VERSION 5.8 ;
BUSBITCHARS "[]" ;
DIVIDERCHAR "/" ;
UNITS
    DATABASE MICRONS 1000 ;
END UNITS

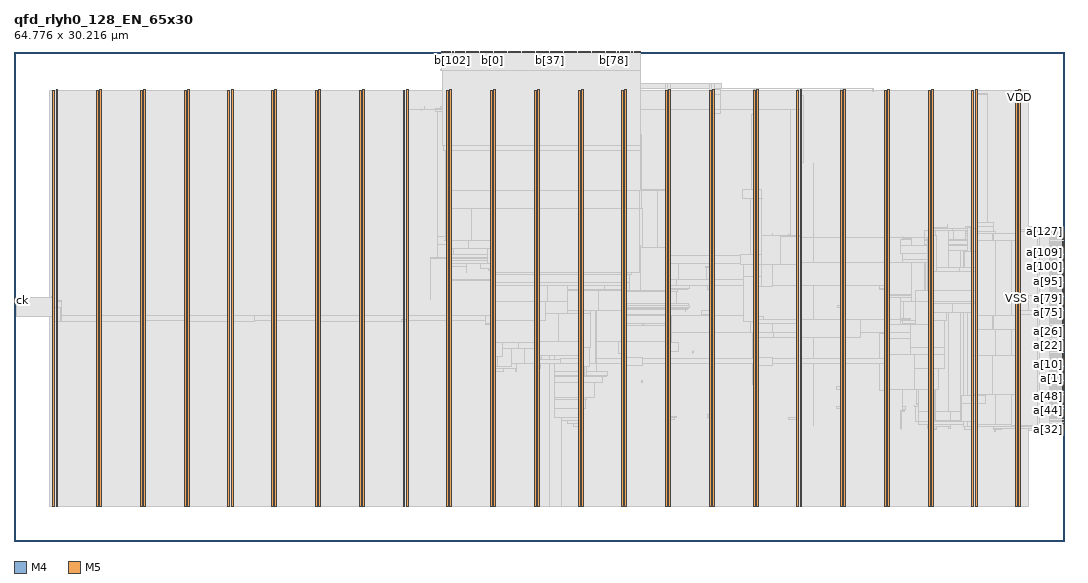
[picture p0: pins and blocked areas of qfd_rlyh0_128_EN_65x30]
MACRO qfd_rlyh0_128_EN_65x30
  FOREIGN qfd_rlyh0_128_EN_65x30 0 0 ;
  CLASS BLOCK ;
  SIZE 64.776 BY 30.216 ;
  PIN a[0]
    DIRECTION INPUT ;
    USE SIGNAL ;
    PORT
      LAYER M4 ;
        RECT  64.692 9.936 64.776 9.96 ;
    END
  END a[0]
  PIN a[100]
    DIRECTION INPUT ;
    USE SIGNAL ;
    PORT
      LAYER M4 ;
        RECT  64.692 16.464 64.776 16.488 ;
    END
  END a[100]
  PIN a[101]
    DIRECTION INPUT ;
    USE SIGNAL ;
    PORT
      LAYER M4 ;
        RECT  64.692 16.56 64.776 16.584 ;
    END
  END a[101]
  PIN a[102]
    DIRECTION INPUT ;
    USE SIGNAL ;
    PORT
      LAYER M4 ;
        RECT  64.692 16.656 64.776 16.68 ;
    END
  END a[102]
  PIN a[103]
    DIRECTION INPUT ;
    USE SIGNAL ;
    PORT
      LAYER M4 ;
        RECT  64.692 16.752 64.776 16.776 ;
    END
  END a[103]
  PIN a[104]
    DIRECTION INPUT ;
    USE SIGNAL ;
    PORT
      LAYER M4 ;
        RECT  64.692 16.848 64.776 16.872 ;
    END
  END a[104]
  PIN a[105]
    DIRECTION INPUT ;
    USE SIGNAL ;
    PORT
      LAYER M4 ;
        RECT  64.692 16.944 64.776 16.968 ;
    END
  END a[105]
  PIN a[106]
    DIRECTION INPUT ;
    USE SIGNAL ;
    PORT
      LAYER M4 ;
        RECT  64.692 17.04 64.776 17.064 ;
    END
  END a[106]
  PIN a[107]
    DIRECTION INPUT ;
    USE SIGNAL ;
    PORT
      LAYER M4 ;
        RECT  64.692 17.136 64.776 17.16 ;
    END
  END a[107]
  PIN a[108]
    DIRECTION INPUT ;
    USE SIGNAL ;
    PORT
      LAYER M4 ;
        RECT  64.692 17.232 64.776 17.256 ;
    END
  END a[108]
  PIN a[109]
    DIRECTION INPUT ;
    USE SIGNAL ;
    PORT
      LAYER M4 ;
        RECT  64.692 17.328 64.776 17.352 ;
    END
  END a[109]
  PIN a[10]
    DIRECTION INPUT ;
    USE SIGNAL ;
    PORT
      LAYER M4 ;
        RECT  64.692 10.896 64.776 10.92 ;
    END
  END a[10]
  PIN a[110]
    DIRECTION INPUT ;
    USE SIGNAL ;
    PORT
      LAYER M4 ;
        RECT  64.692 17.424 64.776 17.448 ;
    END
  END a[110]
  PIN a[111]
    DIRECTION INPUT ;
    USE SIGNAL ;
    PORT
      LAYER M4 ;
        RECT  64.692 17.52 64.776 17.544 ;
    END
  END a[111]
  PIN a[112]
    DIRECTION INPUT ;
    USE SIGNAL ;
    PORT
      LAYER M4 ;
        RECT  64.692 17.616 64.776 17.64 ;
    END
  END a[112]
  PIN a[113]
    DIRECTION INPUT ;
    USE SIGNAL ;
    PORT
      LAYER M4 ;
        RECT  64.692 17.712 64.776 17.736 ;
    END
  END a[113]
  PIN a[114]
    DIRECTION INPUT ;
    USE SIGNAL ;
    PORT
      LAYER M4 ;
        RECT  64.692 17.808 64.776 17.832 ;
    END
  END a[114]
  PIN a[115]
    DIRECTION INPUT ;
    USE SIGNAL ;
    PORT
      LAYER M4 ;
        RECT  64.692 17.904 64.776 17.928 ;
    END
  END a[115]
  PIN a[116]
    DIRECTION INPUT ;
    USE SIGNAL ;
    PORT
      LAYER M4 ;
        RECT  64.692 18 64.776 18.024 ;
    END
  END a[116]
  PIN a[117]
    DIRECTION INPUT ;
    USE SIGNAL ;
    PORT
      LAYER M4 ;
        RECT  64.692 18.096 64.776 18.12 ;
    END
  END a[117]
  PIN a[118]
    DIRECTION INPUT ;
    USE SIGNAL ;
    PORT
      LAYER M4 ;
        RECT  64.692 18.192 64.776 18.216 ;
    END
  END a[118]
  PIN a[119]
    DIRECTION INPUT ;
    USE SIGNAL ;
    PORT
      LAYER M4 ;
        RECT  64.692 18.288 64.776 18.312 ;
    END
  END a[119]
  PIN a[11]
    DIRECTION INPUT ;
    USE SIGNAL ;
    PORT
      LAYER M4 ;
        RECT  64.692 10.992 64.776 11.016 ;
    END
  END a[11]
  PIN a[120]
    DIRECTION INPUT ;
    USE SIGNAL ;
    PORT
      LAYER M4 ;
        RECT  64.692 18.384 64.776 18.408 ;
    END
  END a[120]
  PIN a[121]
    DIRECTION INPUT ;
    USE SIGNAL ;
    PORT
      LAYER M4 ;
        RECT  64.692 18.48 64.776 18.504 ;
    END
  END a[121]
  PIN a[122]
    DIRECTION INPUT ;
    USE SIGNAL ;
    PORT
      LAYER M4 ;
        RECT  64.692 18.576 64.776 18.6 ;
    END
  END a[122]
  PIN a[123]
    DIRECTION INPUT ;
    USE SIGNAL ;
    PORT
      LAYER M4 ;
        RECT  64.692 18.672 64.776 18.696 ;
    END
  END a[123]
  PIN a[124]
    DIRECTION INPUT ;
    USE SIGNAL ;
    PORT
      LAYER M4 ;
        RECT  64.692 18.768 64.776 18.792 ;
    END
  END a[124]
  PIN a[125]
    DIRECTION INPUT ;
    USE SIGNAL ;
    PORT
      LAYER M4 ;
        RECT  64.692 18.864 64.776 18.888 ;
    END
  END a[125]
  PIN a[126]
    DIRECTION INPUT ;
    USE SIGNAL ;
    PORT
      LAYER M4 ;
        RECT  64.692 18.96 64.776 18.984 ;
    END
  END a[126]
  PIN a[127]
    DIRECTION INPUT ;
    USE SIGNAL ;
    PORT
      LAYER M4 ;
        RECT  64.692 19.056 64.776 19.08 ;
    END
  END a[127]
  PIN a[12]
    DIRECTION INPUT ;
    USE SIGNAL ;
    PORT
      LAYER M4 ;
        RECT  64.692 11.088 64.776 11.112 ;
    END
  END a[12]
  PIN a[13]
    DIRECTION INPUT ;
    USE SIGNAL ;
    PORT
      LAYER M4 ;
        RECT  64.692 11.184 64.776 11.208 ;
    END
  END a[13]
  PIN a[14]
    DIRECTION INPUT ;
    USE SIGNAL ;
    PORT
      LAYER M4 ;
        RECT  64.692 11.28 64.776 11.304 ;
    END
  END a[14]
  PIN a[15]
    DIRECTION INPUT ;
    USE SIGNAL ;
    PORT
      LAYER M4 ;
        RECT  64.692 11.376 64.776 11.4 ;
    END
  END a[15]
  PIN a[16]
    DIRECTION INPUT ;
    USE SIGNAL ;
    PORT
      LAYER M4 ;
        RECT  64.692 11.472 64.776 11.496 ;
    END
  END a[16]
  PIN a[17]
    DIRECTION INPUT ;
    USE SIGNAL ;
    PORT
      LAYER M4 ;
        RECT  64.692 11.568 64.776 11.592 ;
    END
  END a[17]
  PIN a[18]
    DIRECTION INPUT ;
    USE SIGNAL ;
    PORT
      LAYER M4 ;
        RECT  64.692 11.664 64.776 11.688 ;
    END
  END a[18]
  PIN a[19]
    DIRECTION INPUT ;
    USE SIGNAL ;
    PORT
      LAYER M4 ;
        RECT  64.692 11.76 64.776 11.784 ;
    END
  END a[19]
  PIN a[1]
    DIRECTION INPUT ;
    USE SIGNAL ;
    PORT
      LAYER M4 ;
        RECT  64.692 10.032 64.776 10.056 ;
    END
  END a[1]
  PIN a[20]
    DIRECTION INPUT ;
    USE SIGNAL ;
    PORT
      LAYER M4 ;
        RECT  64.692 11.856 64.776 11.88 ;
    END
  END a[20]
  PIN a[21]
    DIRECTION INPUT ;
    USE SIGNAL ;
    PORT
      LAYER M4 ;
        RECT  64.692 11.952 64.776 11.976 ;
    END
  END a[21]
  PIN a[22]
    DIRECTION INPUT ;
    USE SIGNAL ;
    PORT
      LAYER M4 ;
        RECT  64.692 12.048 64.776 12.072 ;
    END
  END a[22]
  PIN a[23]
    DIRECTION INPUT ;
    USE SIGNAL ;
    PORT
      LAYER M4 ;
        RECT  64.692 12.144 64.776 12.168 ;
    END
  END a[23]
  PIN a[24]
    DIRECTION INPUT ;
    USE SIGNAL ;
    PORT
      LAYER M4 ;
        RECT  64.692 12.24 64.776 12.264 ;
    END
  END a[24]
  PIN a[25]
    DIRECTION INPUT ;
    USE SIGNAL ;
    PORT
      LAYER M4 ;
        RECT  64.692 12.336 64.776 12.36 ;
    END
  END a[25]
  PIN a[26]
    DIRECTION INPUT ;
    USE SIGNAL ;
    PORT
      LAYER M4 ;
        RECT  64.692 12.432 64.776 12.456 ;
    END
  END a[26]
  PIN a[27]
    DIRECTION INPUT ;
    USE SIGNAL ;
    PORT
      LAYER M4 ;
        RECT  64.692 12.528 64.776 12.552 ;
    END
  END a[27]
  PIN a[28]
    DIRECTION INPUT ;
    USE SIGNAL ;
    PORT
      LAYER M4 ;
        RECT  64.692 12.624 64.776 12.648 ;
    END
  END a[28]
  PIN a[29]
    DIRECTION INPUT ;
    USE SIGNAL ;
    PORT
      LAYER M4 ;
        RECT  64.692 12.72 64.776 12.744 ;
    END
  END a[29]
  PIN a[2]
    DIRECTION INPUT ;
    USE SIGNAL ;
    PORT
      LAYER M4 ;
        RECT  64.692 10.128 64.776 10.152 ;
    END
  END a[2]
  PIN a[30]
    DIRECTION INPUT ;
    USE SIGNAL ;
    PORT
      LAYER M4 ;
        RECT  64.692 12.816 64.776 12.84 ;
    END
  END a[30]
  PIN a[31]
    DIRECTION INPUT ;
    USE SIGNAL ;
    PORT
      LAYER M4 ;
        RECT  64.692 12.912 64.776 12.936 ;
    END
  END a[31]
  PIN a[32]
    DIRECTION INPUT ;
    USE SIGNAL ;
    PORT
      LAYER M4 ;
        RECT  64.692 6.864 64.776 6.888 ;
    END
  END a[32]
  PIN a[33]
    DIRECTION INPUT ;
    USE SIGNAL ;
    PORT
      LAYER M4 ;
        RECT  64.692 6.96 64.776 6.984 ;
    END
  END a[33]
  PIN a[34]
    DIRECTION INPUT ;
    USE SIGNAL ;
    PORT
      LAYER M4 ;
        RECT  64.692 7.056 64.776 7.08 ;
    END
  END a[34]
  PIN a[35]
    DIRECTION INPUT ;
    USE SIGNAL ;
    PORT
      LAYER M4 ;
        RECT  64.692 7.152 64.776 7.176 ;
    END
  END a[35]
  PIN a[36]
    DIRECTION INPUT ;
    USE SIGNAL ;
    PORT
      LAYER M4 ;
        RECT  64.692 7.248 64.776 7.272 ;
    END
  END a[36]
  PIN a[37]
    DIRECTION INPUT ;
    USE SIGNAL ;
    PORT
      LAYER M4 ;
        RECT  64.692 7.344 64.776 7.368 ;
    END
  END a[37]
  PIN a[38]
    DIRECTION INPUT ;
    USE SIGNAL ;
    PORT
      LAYER M4 ;
        RECT  64.692 7.44 64.776 7.464 ;
    END
  END a[38]
  PIN a[39]
    DIRECTION INPUT ;
    USE SIGNAL ;
    PORT
      LAYER M4 ;
        RECT  64.692 7.536 64.776 7.56 ;
    END
  END a[39]
  PIN a[3]
    DIRECTION INPUT ;
    USE SIGNAL ;
    PORT
      LAYER M4 ;
        RECT  64.692 10.224 64.776 10.248 ;
    END
  END a[3]
  PIN a[40]
    DIRECTION INPUT ;
    USE SIGNAL ;
    PORT
      LAYER M4 ;
        RECT  64.692 7.632 64.776 7.656 ;
    END
  END a[40]
  PIN a[41]
    DIRECTION INPUT ;
    USE SIGNAL ;
    PORT
      LAYER M4 ;
        RECT  64.692 7.728 64.776 7.752 ;
    END
  END a[41]
  PIN a[42]
    DIRECTION INPUT ;
    USE SIGNAL ;
    PORT
      LAYER M4 ;
        RECT  64.692 7.824 64.776 7.848 ;
    END
  END a[42]
  PIN a[43]
    DIRECTION INPUT ;
    USE SIGNAL ;
    PORT
      LAYER M4 ;
        RECT  64.692 7.92 64.776 7.944 ;
    END
  END a[43]
  PIN a[44]
    DIRECTION INPUT ;
    USE SIGNAL ;
    PORT
      LAYER M4 ;
        RECT  64.692 8.016 64.776 8.04 ;
    END
  END a[44]
  PIN a[45]
    DIRECTION INPUT ;
    USE SIGNAL ;
    PORT
      LAYER M4 ;
        RECT  64.692 8.112 64.776 8.136 ;
    END
  END a[45]
  PIN a[46]
    DIRECTION INPUT ;
    USE SIGNAL ;
    PORT
      LAYER M4 ;
        RECT  64.692 8.208 64.776 8.232 ;
    END
  END a[46]
  PIN a[47]
    DIRECTION INPUT ;
    USE SIGNAL ;
    PORT
      LAYER M4 ;
        RECT  64.692 8.304 64.776 8.328 ;
    END
  END a[47]
  PIN a[48]
    DIRECTION INPUT ;
    USE SIGNAL ;
    PORT
      LAYER M4 ;
        RECT  64.692 8.4 64.776 8.424 ;
    END
  END a[48]
  PIN a[49]
    DIRECTION INPUT ;
    USE SIGNAL ;
    PORT
      LAYER M4 ;
        RECT  64.692 8.496 64.776 8.52 ;
    END
  END a[49]
  PIN a[4]
    DIRECTION INPUT ;
    USE SIGNAL ;
    PORT
      LAYER M4 ;
        RECT  64.692 10.32 64.776 10.344 ;
    END
  END a[4]
  PIN a[50]
    DIRECTION INPUT ;
    USE SIGNAL ;
    PORT
      LAYER M4 ;
        RECT  64.692 8.592 64.776 8.616 ;
    END
  END a[50]
  PIN a[51]
    DIRECTION INPUT ;
    USE SIGNAL ;
    PORT
      LAYER M4 ;
        RECT  64.692 8.688 64.776 8.712 ;
    END
  END a[51]
  PIN a[52]
    DIRECTION INPUT ;
    USE SIGNAL ;
    PORT
      LAYER M4 ;
        RECT  64.692 8.784 64.776 8.808 ;
    END
  END a[52]
  PIN a[53]
    DIRECTION INPUT ;
    USE SIGNAL ;
    PORT
      LAYER M4 ;
        RECT  64.692 8.88 64.776 8.904 ;
    END
  END a[53]
  PIN a[54]
    DIRECTION INPUT ;
    USE SIGNAL ;
    PORT
      LAYER M4 ;
        RECT  64.692 8.976 64.776 9 ;
    END
  END a[54]
  PIN a[55]
    DIRECTION INPUT ;
    USE SIGNAL ;
    PORT
      LAYER M4 ;
        RECT  64.692 9.072 64.776 9.096 ;
    END
  END a[55]
  PIN a[56]
    DIRECTION INPUT ;
    USE SIGNAL ;
    PORT
      LAYER M4 ;
        RECT  64.692 9.168 64.776 9.192 ;
    END
  END a[56]
  PIN a[57]
    DIRECTION INPUT ;
    USE SIGNAL ;
    PORT
      LAYER M4 ;
        RECT  64.692 9.264 64.776 9.288 ;
    END
  END a[57]
  PIN a[58]
    DIRECTION INPUT ;
    USE SIGNAL ;
    PORT
      LAYER M4 ;
        RECT  64.692 9.36 64.776 9.384 ;
    END
  END a[58]
  PIN a[59]
    DIRECTION INPUT ;
    USE SIGNAL ;
    PORT
      LAYER M4 ;
        RECT  64.692 9.456 64.776 9.48 ;
    END
  END a[59]
  PIN a[5]
    DIRECTION INPUT ;
    USE SIGNAL ;
    PORT
      LAYER M4 ;
        RECT  64.692 10.416 64.776 10.44 ;
    END
  END a[5]
  PIN a[60]
    DIRECTION INPUT ;
    USE SIGNAL ;
    PORT
      LAYER M4 ;
        RECT  64.692 9.552 64.776 9.576 ;
    END
  END a[60]
  PIN a[61]
    DIRECTION INPUT ;
    USE SIGNAL ;
    PORT
      LAYER M4 ;
        RECT  64.692 9.648 64.776 9.672 ;
    END
  END a[61]
  PIN a[62]
    DIRECTION INPUT ;
    USE SIGNAL ;
    PORT
      LAYER M4 ;
        RECT  64.692 9.744 64.776 9.768 ;
    END
  END a[62]
  PIN a[63]
    DIRECTION INPUT ;
    USE SIGNAL ;
    PORT
      LAYER M4 ;
        RECT  64.692 9.84 64.776 9.864 ;
    END
  END a[63]
  PIN a[64]
    DIRECTION INPUT ;
    USE SIGNAL ;
    PORT
      LAYER M4 ;
        RECT  64.692 13.008 64.776 13.032 ;
    END
  END a[64]
  PIN a[65]
    DIRECTION INPUT ;
    USE SIGNAL ;
    PORT
      LAYER M4 ;
        RECT  64.692 13.104 64.776 13.128 ;
    END
  END a[65]
  PIN a[66]
    DIRECTION INPUT ;
    USE SIGNAL ;
    PORT
      LAYER M4 ;
        RECT  64.692 13.2 64.776 13.224 ;
    END
  END a[66]
  PIN a[67]
    DIRECTION INPUT ;
    USE SIGNAL ;
    PORT
      LAYER M4 ;
        RECT  64.692 13.296 64.776 13.32 ;
    END
  END a[67]
  PIN a[68]
    DIRECTION INPUT ;
    USE SIGNAL ;
    PORT
      LAYER M4 ;
        RECT  64.692 13.392 64.776 13.416 ;
    END
  END a[68]
  PIN a[69]
    DIRECTION INPUT ;
    USE SIGNAL ;
    PORT
      LAYER M4 ;
        RECT  64.692 13.488 64.776 13.512 ;
    END
  END a[69]
  PIN a[6]
    DIRECTION INPUT ;
    USE SIGNAL ;
    PORT
      LAYER M4 ;
        RECT  64.692 10.512 64.776 10.536 ;
    END
  END a[6]
  PIN a[70]
    DIRECTION INPUT ;
    USE SIGNAL ;
    PORT
      LAYER M4 ;
        RECT  64.692 13.584 64.776 13.608 ;
    END
  END a[70]
  PIN a[71]
    DIRECTION INPUT ;
    USE SIGNAL ;
    PORT
      LAYER M4 ;
        RECT  64.692 13.68 64.776 13.704 ;
    END
  END a[71]
  PIN a[72]
    DIRECTION INPUT ;
    USE SIGNAL ;
    PORT
      LAYER M4 ;
        RECT  64.692 13.776 64.776 13.8 ;
    END
  END a[72]
  PIN a[73]
    DIRECTION INPUT ;
    USE SIGNAL ;
    PORT
      LAYER M4 ;
        RECT  64.692 13.872 64.776 13.896 ;
    END
  END a[73]
  PIN a[74]
    DIRECTION INPUT ;
    USE SIGNAL ;
    PORT
      LAYER M4 ;
        RECT  64.692 13.968 64.776 13.992 ;
    END
  END a[74]
  PIN a[75]
    DIRECTION INPUT ;
    USE SIGNAL ;
    PORT
      LAYER M4 ;
        RECT  64.692 14.064 64.776 14.088 ;
    END
  END a[75]
  PIN a[76]
    DIRECTION INPUT ;
    USE SIGNAL ;
    PORT
      LAYER M4 ;
        RECT  64.692 14.16 64.776 14.184 ;
    END
  END a[76]
  PIN a[77]
    DIRECTION INPUT ;
    USE SIGNAL ;
    PORT
      LAYER M4 ;
        RECT  64.692 14.256 64.776 14.28 ;
    END
  END a[77]
  PIN a[78]
    DIRECTION INPUT ;
    USE SIGNAL ;
    PORT
      LAYER M4 ;
        RECT  64.692 14.352 64.776 14.376 ;
    END
  END a[78]
  PIN a[79]
    DIRECTION INPUT ;
    USE SIGNAL ;
    PORT
      LAYER M4 ;
        RECT  64.692 14.448 64.776 14.472 ;
    END
  END a[79]
  PIN a[7]
    DIRECTION INPUT ;
    USE SIGNAL ;
    PORT
      LAYER M4 ;
        RECT  64.692 10.608 64.776 10.632 ;
    END
  END a[7]
  PIN a[80]
    DIRECTION INPUT ;
    USE SIGNAL ;
    PORT
      LAYER M4 ;
        RECT  64.692 14.544 64.776 14.568 ;
    END
  END a[80]
  PIN a[81]
    DIRECTION INPUT ;
    USE SIGNAL ;
    PORT
      LAYER M4 ;
        RECT  64.692 14.64 64.776 14.664 ;
    END
  END a[81]
  PIN a[82]
    DIRECTION INPUT ;
    USE SIGNAL ;
    PORT
      LAYER M4 ;
        RECT  64.692 14.736 64.776 14.76 ;
    END
  END a[82]
  PIN a[83]
    DIRECTION INPUT ;
    USE SIGNAL ;
    PORT
      LAYER M4 ;
        RECT  64.692 14.832 64.776 14.856 ;
    END
  END a[83]
  PIN a[84]
    DIRECTION INPUT ;
    USE SIGNAL ;
    PORT
      LAYER M4 ;
        RECT  64.692 14.928 64.776 14.952 ;
    END
  END a[84]
  PIN a[85]
    DIRECTION INPUT ;
    USE SIGNAL ;
    PORT
      LAYER M4 ;
        RECT  64.692 15.024 64.776 15.048 ;
    END
  END a[85]
  PIN a[86]
    DIRECTION INPUT ;
    USE SIGNAL ;
    PORT
      LAYER M4 ;
        RECT  64.692 15.12 64.776 15.144 ;
    END
  END a[86]
  PIN a[87]
    DIRECTION INPUT ;
    USE SIGNAL ;
    PORT
      LAYER M4 ;
        RECT  64.692 15.216 64.776 15.24 ;
    END
  END a[87]
  PIN a[88]
    DIRECTION INPUT ;
    USE SIGNAL ;
    PORT
      LAYER M4 ;
        RECT  64.692 15.312 64.776 15.336 ;
    END
  END a[88]
  PIN a[89]
    DIRECTION INPUT ;
    USE SIGNAL ;
    PORT
      LAYER M4 ;
        RECT  64.692 15.408 64.776 15.432 ;
    END
  END a[89]
  PIN a[8]
    DIRECTION INPUT ;
    USE SIGNAL ;
    PORT
      LAYER M4 ;
        RECT  64.692 10.704 64.776 10.728 ;
    END
  END a[8]
  PIN a[90]
    DIRECTION INPUT ;
    USE SIGNAL ;
    PORT
      LAYER M4 ;
        RECT  64.692 15.504 64.776 15.528 ;
    END
  END a[90]
  PIN a[91]
    DIRECTION INPUT ;
    USE SIGNAL ;
    PORT
      LAYER M4 ;
        RECT  64.692 15.6 64.776 15.624 ;
    END
  END a[91]
  PIN a[92]
    DIRECTION INPUT ;
    USE SIGNAL ;
    PORT
      LAYER M4 ;
        RECT  64.692 15.696 64.776 15.72 ;
    END
  END a[92]
  PIN a[93]
    DIRECTION INPUT ;
    USE SIGNAL ;
    PORT
      LAYER M4 ;
        RECT  64.692 15.792 64.776 15.816 ;
    END
  END a[93]
  PIN a[94]
    DIRECTION INPUT ;
    USE SIGNAL ;
    PORT
      LAYER M4 ;
        RECT  64.692 15.888 64.776 15.912 ;
    END
  END a[94]
  PIN a[95]
    DIRECTION INPUT ;
    USE SIGNAL ;
    PORT
      LAYER M4 ;
        RECT  64.692 15.984 64.776 16.008 ;
    END
  END a[95]
  PIN a[96]
    DIRECTION INPUT ;
    USE SIGNAL ;
    PORT
      LAYER M4 ;
        RECT  64.692 16.08 64.776 16.104 ;
    END
  END a[96]
  PIN a[97]
    DIRECTION INPUT ;
    USE SIGNAL ;
    PORT
      LAYER M4 ;
        RECT  64.692 16.176 64.776 16.2 ;
    END
  END a[97]
  PIN a[98]
    DIRECTION INPUT ;
    USE SIGNAL ;
    PORT
      LAYER M4 ;
        RECT  64.692 16.272 64.776 16.296 ;
    END
  END a[98]
  PIN a[99]
    DIRECTION INPUT ;
    USE SIGNAL ;
    PORT
      LAYER M4 ;
        RECT  64.692 16.368 64.776 16.392 ;
    END
  END a[99]
  PIN a[9]
    DIRECTION INPUT ;
    USE SIGNAL ;
    PORT
      LAYER M4 ;
        RECT  64.692 10.8 64.776 10.824 ;
    END
  END a[9]
  PIN b[0]
    DIRECTION OUTPUT ;
    USE SIGNAL ;
    PORT
      LAYER M5 ;
        RECT  29.52 30.132 29.544 30.216 ;
    END
  END b[0]
  PIN b[100]
    DIRECTION OUTPUT ;
    USE SIGNAL ;
    PORT
      LAYER M5 ;
        RECT  26.832 30.132 26.856 30.216 ;
    END
  END b[100]
  PIN b[101]
    DIRECTION OUTPUT ;
    USE SIGNAL ;
    PORT
      LAYER M5 ;
        RECT  26.928 30.132 26.952 30.216 ;
    END
  END b[101]
  PIN b[102]
    DIRECTION OUTPUT ;
    USE SIGNAL ;
    PORT
      LAYER M5 ;
        RECT  27.024 30.132 27.048 30.216 ;
    END
  END b[102]
  PIN b[103]
    DIRECTION OUTPUT ;
    USE SIGNAL ;
    PORT
      LAYER M5 ;
        RECT  27.12 30.132 27.144 30.216 ;
    END
  END b[103]
  PIN b[104]
    DIRECTION OUTPUT ;
    USE SIGNAL ;
    PORT
      LAYER M5 ;
        RECT  27.216 30.132 27.24 30.216 ;
    END
  END b[104]
  PIN b[105]
    DIRECTION OUTPUT ;
    USE SIGNAL ;
    PORT
      LAYER M5 ;
        RECT  27.312 30.132 27.336 30.216 ;
    END
  END b[105]
  PIN b[106]
    DIRECTION OUTPUT ;
    USE SIGNAL ;
    PORT
      LAYER M5 ;
        RECT  27.408 30.132 27.432 30.216 ;
    END
  END b[106]
  PIN b[107]
    DIRECTION OUTPUT ;
    USE SIGNAL ;
    PORT
      LAYER M5 ;
        RECT  27.504 30.132 27.528 30.216 ;
    END
  END b[107]
  PIN b[108]
    DIRECTION OUTPUT ;
    USE SIGNAL ;
    PORT
      LAYER M5 ;
        RECT  27.6 30.132 27.624 30.216 ;
    END
  END b[108]
  PIN b[109]
    DIRECTION OUTPUT ;
    USE SIGNAL ;
    PORT
      LAYER M5 ;
        RECT  27.696 30.132 27.72 30.216 ;
    END
  END b[109]
  PIN b[10]
    DIRECTION OUTPUT ;
    USE SIGNAL ;
    PORT
      LAYER M5 ;
        RECT  30.48 30.132 30.504 30.216 ;
    END
  END b[10]
  PIN b[110]
    DIRECTION OUTPUT ;
    USE SIGNAL ;
    PORT
      LAYER M5 ;
        RECT  27.792 30.132 27.816 30.216 ;
    END
  END b[110]
  PIN b[111]
    DIRECTION OUTPUT ;
    USE SIGNAL ;
    PORT
      LAYER M5 ;
        RECT  27.888 30.132 27.912 30.216 ;
    END
  END b[111]
  PIN b[112]
    DIRECTION OUTPUT ;
    USE SIGNAL ;
    PORT
      LAYER M5 ;
        RECT  27.984 30.132 28.008 30.216 ;
    END
  END b[112]
  PIN b[113]
    DIRECTION OUTPUT ;
    USE SIGNAL ;
    PORT
      LAYER M5 ;
        RECT  28.08 30.132 28.104 30.216 ;
    END
  END b[113]
  PIN b[114]
    DIRECTION OUTPUT ;
    USE SIGNAL ;
    PORT
      LAYER M5 ;
        RECT  28.176 30.132 28.2 30.216 ;
    END
  END b[114]
  PIN b[115]
    DIRECTION OUTPUT ;
    USE SIGNAL ;
    PORT
      LAYER M5 ;
        RECT  28.272 30.132 28.296 30.216 ;
    END
  END b[115]
  PIN b[116]
    DIRECTION OUTPUT ;
    USE SIGNAL ;
    PORT
      LAYER M5 ;
        RECT  28.368 30.132 28.392 30.216 ;
    END
  END b[116]
  PIN b[117]
    DIRECTION OUTPUT ;
    USE SIGNAL ;
    PORT
      LAYER M5 ;
        RECT  28.464 30.132 28.488 30.216 ;
    END
  END b[117]
  PIN b[118]
    DIRECTION OUTPUT ;
    USE SIGNAL ;
    PORT
      LAYER M5 ;
        RECT  28.56 30.132 28.584 30.216 ;
    END
  END b[118]
  PIN b[119]
    DIRECTION OUTPUT ;
    USE SIGNAL ;
    PORT
      LAYER M5 ;
        RECT  28.656 30.132 28.68 30.216 ;
    END
  END b[119]
  PIN b[11]
    DIRECTION OUTPUT ;
    USE SIGNAL ;
    PORT
      LAYER M5 ;
        RECT  30.576 30.132 30.6 30.216 ;
    END
  END b[11]
  PIN b[120]
    DIRECTION OUTPUT ;
    USE SIGNAL ;
    PORT
      LAYER M5 ;
        RECT  28.752 30.132 28.776 30.216 ;
    END
  END b[120]
  PIN b[121]
    DIRECTION OUTPUT ;
    USE SIGNAL ;
    PORT
      LAYER M5 ;
        RECT  28.848 30.132 28.872 30.216 ;
    END
  END b[121]
  PIN b[122]
    DIRECTION OUTPUT ;
    USE SIGNAL ;
    PORT
      LAYER M5 ;
        RECT  28.944 30.132 28.968 30.216 ;
    END
  END b[122]
  PIN b[123]
    DIRECTION OUTPUT ;
    USE SIGNAL ;
    PORT
      LAYER M5 ;
        RECT  29.04 30.132 29.064 30.216 ;
    END
  END b[123]
  PIN b[124]
    DIRECTION OUTPUT ;
    USE SIGNAL ;
    PORT
      LAYER M5 ;
        RECT  29.136 30.132 29.16 30.216 ;
    END
  END b[124]
  PIN b[125]
    DIRECTION OUTPUT ;
    USE SIGNAL ;
    PORT
      LAYER M5 ;
        RECT  29.232 30.132 29.256 30.216 ;
    END
  END b[125]
  PIN b[126]
    DIRECTION OUTPUT ;
    USE SIGNAL ;
    PORT
      LAYER M5 ;
        RECT  29.328 30.132 29.352 30.216 ;
    END
  END b[126]
  PIN b[127]
    DIRECTION OUTPUT ;
    USE SIGNAL ;
    PORT
      LAYER M5 ;
        RECT  29.424 30.132 29.448 30.216 ;
    END
  END b[127]
  PIN b[12]
    DIRECTION OUTPUT ;
    USE SIGNAL ;
    PORT
      LAYER M5 ;
        RECT  30.672 30.132 30.696 30.216 ;
    END
  END b[12]
  PIN b[13]
    DIRECTION OUTPUT ;
    USE SIGNAL ;
    PORT
      LAYER M5 ;
        RECT  30.768 30.132 30.792 30.216 ;
    END
  END b[13]
  PIN b[14]
    DIRECTION OUTPUT ;
    USE SIGNAL ;
    PORT
      LAYER M5 ;
        RECT  30.864 30.132 30.888 30.216 ;
    END
  END b[14]
  PIN b[15]
    DIRECTION OUTPUT ;
    USE SIGNAL ;
    PORT
      LAYER M5 ;
        RECT  30.96 30.132 30.984 30.216 ;
    END
  END b[15]
  PIN b[16]
    DIRECTION OUTPUT ;
    USE SIGNAL ;
    PORT
      LAYER M5 ;
        RECT  31.056 30.132 31.08 30.216 ;
    END
  END b[16]
  PIN b[17]
    DIRECTION OUTPUT ;
    USE SIGNAL ;
    PORT
      LAYER M5 ;
        RECT  31.152 30.132 31.176 30.216 ;
    END
  END b[17]
  PIN b[18]
    DIRECTION OUTPUT ;
    USE SIGNAL ;
    PORT
      LAYER M5 ;
        RECT  31.248 30.132 31.272 30.216 ;
    END
  END b[18]
  PIN b[19]
    DIRECTION OUTPUT ;
    USE SIGNAL ;
    PORT
      LAYER M5 ;
        RECT  31.344 30.132 31.368 30.216 ;
    END
  END b[19]
  PIN b[1]
    DIRECTION OUTPUT ;
    USE SIGNAL ;
    PORT
      LAYER M5 ;
        RECT  29.616 30.132 29.64 30.216 ;
    END
  END b[1]
  PIN b[20]
    DIRECTION OUTPUT ;
    USE SIGNAL ;
    PORT
      LAYER M5 ;
        RECT  31.44 30.132 31.464 30.216 ;
    END
  END b[20]
  PIN b[21]
    DIRECTION OUTPUT ;
    USE SIGNAL ;
    PORT
      LAYER M5 ;
        RECT  31.536 30.132 31.56 30.216 ;
    END
  END b[21]
  PIN b[22]
    DIRECTION OUTPUT ;
    USE SIGNAL ;
    PORT
      LAYER M5 ;
        RECT  31.632 30.132 31.656 30.216 ;
    END
  END b[22]
  PIN b[23]
    DIRECTION OUTPUT ;
    USE SIGNAL ;
    PORT
      LAYER M5 ;
        RECT  31.728 30.132 31.752 30.216 ;
    END
  END b[23]
  PIN b[24]
    DIRECTION OUTPUT ;
    USE SIGNAL ;
    PORT
      LAYER M5 ;
        RECT  31.824 30.132 31.848 30.216 ;
    END
  END b[24]
  PIN b[25]
    DIRECTION OUTPUT ;
    USE SIGNAL ;
    PORT
      LAYER M5 ;
        RECT  31.92 30.132 31.944 30.216 ;
    END
  END b[25]
  PIN b[26]
    DIRECTION OUTPUT ;
    USE SIGNAL ;
    PORT
      LAYER M5 ;
        RECT  32.016 30.132 32.04 30.216 ;
    END
  END b[26]
  PIN b[27]
    DIRECTION OUTPUT ;
    USE SIGNAL ;
    PORT
      LAYER M5 ;
        RECT  32.112 30.132 32.136 30.216 ;
    END
  END b[27]
  PIN b[28]
    DIRECTION OUTPUT ;
    USE SIGNAL ;
    PORT
      LAYER M5 ;
        RECT  32.208 30.132 32.232 30.216 ;
    END
  END b[28]
  PIN b[29]
    DIRECTION OUTPUT ;
    USE SIGNAL ;
    PORT
      LAYER M5 ;
        RECT  32.304 30.132 32.328 30.216 ;
    END
  END b[29]
  PIN b[2]
    DIRECTION OUTPUT ;
    USE SIGNAL ;
    PORT
      LAYER M5 ;
        RECT  29.712 30.132 29.736 30.216 ;
    END
  END b[2]
  PIN b[30]
    DIRECTION OUTPUT ;
    USE SIGNAL ;
    PORT
      LAYER M5 ;
        RECT  32.4 30.132 32.424 30.216 ;
    END
  END b[30]
  PIN b[31]
    DIRECTION OUTPUT ;
    USE SIGNAL ;
    PORT
      LAYER M5 ;
        RECT  32.496 30.132 32.52 30.216 ;
    END
  END b[31]
  PIN b[32]
    DIRECTION OUTPUT ;
    USE SIGNAL ;
    PORT
      LAYER M5 ;
        RECT  32.592 30.132 32.616 30.216 ;
    END
  END b[32]
  PIN b[33]
    DIRECTION OUTPUT ;
    USE SIGNAL ;
    PORT
      LAYER M5 ;
        RECT  32.688 30.132 32.712 30.216 ;
    END
  END b[33]
  PIN b[34]
    DIRECTION OUTPUT ;
    USE SIGNAL ;
    PORT
      LAYER M5 ;
        RECT  32.784 30.132 32.808 30.216 ;
    END
  END b[34]
  PIN b[35]
    DIRECTION OUTPUT ;
    USE SIGNAL ;
    PORT
      LAYER M5 ;
        RECT  32.88 30.132 32.904 30.216 ;
    END
  END b[35]
  PIN b[36]
    DIRECTION OUTPUT ;
    USE SIGNAL ;
    PORT
      LAYER M5 ;
        RECT  32.976 30.132 33 30.216 ;
    END
  END b[36]
  PIN b[37]
    DIRECTION OUTPUT ;
    USE SIGNAL ;
    PORT
      LAYER M5 ;
        RECT  33.072 30.132 33.096 30.216 ;
    END
  END b[37]
  PIN b[38]
    DIRECTION OUTPUT ;
    USE SIGNAL ;
    PORT
      LAYER M5 ;
        RECT  33.168 30.132 33.192 30.216 ;
    END
  END b[38]
  PIN b[39]
    DIRECTION OUTPUT ;
    USE SIGNAL ;
    PORT
      LAYER M5 ;
        RECT  33.264 30.132 33.288 30.216 ;
    END
  END b[39]
  PIN b[3]
    DIRECTION OUTPUT ;
    USE SIGNAL ;
    PORT
      LAYER M5 ;
        RECT  29.808 30.132 29.832 30.216 ;
    END
  END b[3]
  PIN b[40]
    DIRECTION OUTPUT ;
    USE SIGNAL ;
    PORT
      LAYER M5 ;
        RECT  33.36 30.132 33.384 30.216 ;
    END
  END b[40]
  PIN b[41]
    DIRECTION OUTPUT ;
    USE SIGNAL ;
    PORT
      LAYER M5 ;
        RECT  33.456 30.132 33.48 30.216 ;
    END
  END b[41]
  PIN b[42]
    DIRECTION OUTPUT ;
    USE SIGNAL ;
    PORT
      LAYER M5 ;
        RECT  33.552 30.132 33.576 30.216 ;
    END
  END b[42]
  PIN b[43]
    DIRECTION OUTPUT ;
    USE SIGNAL ;
    PORT
      LAYER M5 ;
        RECT  33.648 30.132 33.672 30.216 ;
    END
  END b[43]
  PIN b[44]
    DIRECTION OUTPUT ;
    USE SIGNAL ;
    PORT
      LAYER M5 ;
        RECT  33.744 30.132 33.768 30.216 ;
    END
  END b[44]
  PIN b[45]
    DIRECTION OUTPUT ;
    USE SIGNAL ;
    PORT
      LAYER M5 ;
        RECT  33.84 30.132 33.864 30.216 ;
    END
  END b[45]
  PIN b[46]
    DIRECTION OUTPUT ;
    USE SIGNAL ;
    PORT
      LAYER M5 ;
        RECT  33.936 30.132 33.96 30.216 ;
    END
  END b[46]
  PIN b[47]
    DIRECTION OUTPUT ;
    USE SIGNAL ;
    PORT
      LAYER M5 ;
        RECT  34.032 30.132 34.056 30.216 ;
    END
  END b[47]
  PIN b[48]
    DIRECTION OUTPUT ;
    USE SIGNAL ;
    PORT
      LAYER M5 ;
        RECT  34.128 30.132 34.152 30.216 ;
    END
  END b[48]
  PIN b[49]
    DIRECTION OUTPUT ;
    USE SIGNAL ;
    PORT
      LAYER M5 ;
        RECT  34.224 30.132 34.248 30.216 ;
    END
  END b[49]
  PIN b[4]
    DIRECTION OUTPUT ;
    USE SIGNAL ;
    PORT
      LAYER M5 ;
        RECT  29.904 30.132 29.928 30.216 ;
    END
  END b[4]
  PIN b[50]
    DIRECTION OUTPUT ;
    USE SIGNAL ;
    PORT
      LAYER M5 ;
        RECT  34.32 30.132 34.344 30.216 ;
    END
  END b[50]
  PIN b[51]
    DIRECTION OUTPUT ;
    USE SIGNAL ;
    PORT
      LAYER M5 ;
        RECT  34.416 30.132 34.44 30.216 ;
    END
  END b[51]
  PIN b[52]
    DIRECTION OUTPUT ;
    USE SIGNAL ;
    PORT
      LAYER M5 ;
        RECT  34.512 30.132 34.536 30.216 ;
    END
  END b[52]
  PIN b[53]
    DIRECTION OUTPUT ;
    USE SIGNAL ;
    PORT
      LAYER M5 ;
        RECT  34.608 30.132 34.632 30.216 ;
    END
  END b[53]
  PIN b[54]
    DIRECTION OUTPUT ;
    USE SIGNAL ;
    PORT
      LAYER M5 ;
        RECT  34.704 30.132 34.728 30.216 ;
    END
  END b[54]
  PIN b[55]
    DIRECTION OUTPUT ;
    USE SIGNAL ;
    PORT
      LAYER M5 ;
        RECT  34.8 30.132 34.824 30.216 ;
    END
  END b[55]
  PIN b[56]
    DIRECTION OUTPUT ;
    USE SIGNAL ;
    PORT
      LAYER M5 ;
        RECT  34.896 30.132 34.92 30.216 ;
    END
  END b[56]
  PIN b[57]
    DIRECTION OUTPUT ;
    USE SIGNAL ;
    PORT
      LAYER M5 ;
        RECT  34.992 30.132 35.016 30.216 ;
    END
  END b[57]
  PIN b[58]
    DIRECTION OUTPUT ;
    USE SIGNAL ;
    PORT
      LAYER M5 ;
        RECT  35.088 30.132 35.112 30.216 ;
    END
  END b[58]
  PIN b[59]
    DIRECTION OUTPUT ;
    USE SIGNAL ;
    PORT
      LAYER M5 ;
        RECT  35.184 30.132 35.208 30.216 ;
    END
  END b[59]
  PIN b[5]
    DIRECTION OUTPUT ;
    USE SIGNAL ;
    PORT
      LAYER M5 ;
        RECT  30 30.132 30.024 30.216 ;
    END
  END b[5]
  PIN b[60]
    DIRECTION OUTPUT ;
    USE SIGNAL ;
    PORT
      LAYER M5 ;
        RECT  35.28 30.132 35.304 30.216 ;
    END
  END b[60]
  PIN b[61]
    DIRECTION OUTPUT ;
    USE SIGNAL ;
    PORT
      LAYER M5 ;
        RECT  35.376 30.132 35.4 30.216 ;
    END
  END b[61]
  PIN b[62]
    DIRECTION OUTPUT ;
    USE SIGNAL ;
    PORT
      LAYER M5 ;
        RECT  35.472 30.132 35.496 30.216 ;
    END
  END b[62]
  PIN b[63]
    DIRECTION OUTPUT ;
    USE SIGNAL ;
    PORT
      LAYER M5 ;
        RECT  35.568 30.132 35.592 30.216 ;
    END
  END b[63]
  PIN b[64]
    DIRECTION OUTPUT ;
    USE SIGNAL ;
    PORT
      LAYER M5 ;
        RECT  35.664 30.132 35.688 30.216 ;
    END
  END b[64]
  PIN b[65]
    DIRECTION OUTPUT ;
    USE SIGNAL ;
    PORT
      LAYER M5 ;
        RECT  35.76 30.132 35.784 30.216 ;
    END
  END b[65]
  PIN b[66]
    DIRECTION OUTPUT ;
    USE SIGNAL ;
    PORT
      LAYER M5 ;
        RECT  35.856 30.132 35.88 30.216 ;
    END
  END b[66]
  PIN b[67]
    DIRECTION OUTPUT ;
    USE SIGNAL ;
    PORT
      LAYER M5 ;
        RECT  35.952 30.132 35.976 30.216 ;
    END
  END b[67]
  PIN b[68]
    DIRECTION OUTPUT ;
    USE SIGNAL ;
    PORT
      LAYER M5 ;
        RECT  36.048 30.132 36.072 30.216 ;
    END
  END b[68]
  PIN b[69]
    DIRECTION OUTPUT ;
    USE SIGNAL ;
    PORT
      LAYER M5 ;
        RECT  36.144 30.132 36.168 30.216 ;
    END
  END b[69]
  PIN b[6]
    DIRECTION OUTPUT ;
    USE SIGNAL ;
    PORT
      LAYER M5 ;
        RECT  30.096 30.132 30.12 30.216 ;
    END
  END b[6]
  PIN b[70]
    DIRECTION OUTPUT ;
    USE SIGNAL ;
    PORT
      LAYER M5 ;
        RECT  36.24 30.132 36.264 30.216 ;
    END
  END b[70]
  PIN b[71]
    DIRECTION OUTPUT ;
    USE SIGNAL ;
    PORT
      LAYER M5 ;
        RECT  36.336 30.132 36.36 30.216 ;
    END
  END b[71]
  PIN b[72]
    DIRECTION OUTPUT ;
    USE SIGNAL ;
    PORT
      LAYER M5 ;
        RECT  36.432 30.132 36.456 30.216 ;
    END
  END b[72]
  PIN b[73]
    DIRECTION OUTPUT ;
    USE SIGNAL ;
    PORT
      LAYER M5 ;
        RECT  36.528 30.132 36.552 30.216 ;
    END
  END b[73]
  PIN b[74]
    DIRECTION OUTPUT ;
    USE SIGNAL ;
    PORT
      LAYER M5 ;
        RECT  36.624 30.132 36.648 30.216 ;
    END
  END b[74]
  PIN b[75]
    DIRECTION OUTPUT ;
    USE SIGNAL ;
    PORT
      LAYER M5 ;
        RECT  36.72 30.132 36.744 30.216 ;
    END
  END b[75]
  PIN b[76]
    DIRECTION OUTPUT ;
    USE SIGNAL ;
    PORT
      LAYER M5 ;
        RECT  36.816 30.132 36.84 30.216 ;
    END
  END b[76]
  PIN b[77]
    DIRECTION OUTPUT ;
    USE SIGNAL ;
    PORT
      LAYER M5 ;
        RECT  36.912 30.132 36.936 30.216 ;
    END
  END b[77]
  PIN b[78]
    DIRECTION OUTPUT ;
    USE SIGNAL ;
    PORT
      LAYER M5 ;
        RECT  37.008 30.132 37.032 30.216 ;
    END
  END b[78]
  PIN b[79]
    DIRECTION OUTPUT ;
    USE SIGNAL ;
    PORT
      LAYER M5 ;
        RECT  37.104 30.132 37.128 30.216 ;
    END
  END b[79]
  PIN b[7]
    DIRECTION OUTPUT ;
    USE SIGNAL ;
    PORT
      LAYER M5 ;
        RECT  30.192 30.132 30.216 30.216 ;
    END
  END b[7]
  PIN b[80]
    DIRECTION OUTPUT ;
    USE SIGNAL ;
    PORT
      LAYER M5 ;
        RECT  37.2 30.132 37.224 30.216 ;
    END
  END b[80]
  PIN b[81]
    DIRECTION OUTPUT ;
    USE SIGNAL ;
    PORT
      LAYER M5 ;
        RECT  37.296 30.132 37.32 30.216 ;
    END
  END b[81]
  PIN b[82]
    DIRECTION OUTPUT ;
    USE SIGNAL ;
    PORT
      LAYER M5 ;
        RECT  37.392 30.132 37.416 30.216 ;
    END
  END b[82]
  PIN b[83]
    DIRECTION OUTPUT ;
    USE SIGNAL ;
    PORT
      LAYER M5 ;
        RECT  37.488 30.132 37.512 30.216 ;
    END
  END b[83]
  PIN b[84]
    DIRECTION OUTPUT ;
    USE SIGNAL ;
    PORT
      LAYER M5 ;
        RECT  37.584 30.132 37.608 30.216 ;
    END
  END b[84]
  PIN b[85]
    DIRECTION OUTPUT ;
    USE SIGNAL ;
    PORT
      LAYER M5 ;
        RECT  37.68 30.132 37.704 30.216 ;
    END
  END b[85]
  PIN b[86]
    DIRECTION OUTPUT ;
    USE SIGNAL ;
    PORT
      LAYER M5 ;
        RECT  37.776 30.132 37.8 30.216 ;
    END
  END b[86]
  PIN b[87]
    DIRECTION OUTPUT ;
    USE SIGNAL ;
    PORT
      LAYER M5 ;
        RECT  37.872 30.132 37.896 30.216 ;
    END
  END b[87]
  PIN b[88]
    DIRECTION OUTPUT ;
    USE SIGNAL ;
    PORT
      LAYER M5 ;
        RECT  37.968 30.132 37.992 30.216 ;
    END
  END b[88]
  PIN b[89]
    DIRECTION OUTPUT ;
    USE SIGNAL ;
    PORT
      LAYER M5 ;
        RECT  38.064 30.132 38.088 30.216 ;
    END
  END b[89]
  PIN b[8]
    DIRECTION OUTPUT ;
    USE SIGNAL ;
    PORT
      LAYER M5 ;
        RECT  30.288 30.132 30.312 30.216 ;
    END
  END b[8]
  PIN b[90]
    DIRECTION OUTPUT ;
    USE SIGNAL ;
    PORT
      LAYER M5 ;
        RECT  38.16 30.132 38.184 30.216 ;
    END
  END b[90]
  PIN b[91]
    DIRECTION OUTPUT ;
    USE SIGNAL ;
    PORT
      LAYER M5 ;
        RECT  38.256 30.132 38.28 30.216 ;
    END
  END b[91]
  PIN b[92]
    DIRECTION OUTPUT ;
    USE SIGNAL ;
    PORT
      LAYER M5 ;
        RECT  38.352 30.132 38.376 30.216 ;
    END
  END b[92]
  PIN b[93]
    DIRECTION OUTPUT ;
    USE SIGNAL ;
    PORT
      LAYER M5 ;
        RECT  38.448 30.132 38.472 30.216 ;
    END
  END b[93]
  PIN b[94]
    DIRECTION OUTPUT ;
    USE SIGNAL ;
    PORT
      LAYER M5 ;
        RECT  38.544 30.132 38.568 30.216 ;
    END
  END b[94]
  PIN b[95]
    DIRECTION OUTPUT ;
    USE SIGNAL ;
    PORT
      LAYER M5 ;
        RECT  38.64 30.132 38.664 30.216 ;
    END
  END b[95]
  PIN b[96]
    DIRECTION OUTPUT ;
    USE SIGNAL ;
    PORT
      LAYER M5 ;
        RECT  26.448 30.132 26.472 30.216 ;
    END
  END b[96]
  PIN b[97]
    DIRECTION OUTPUT ;
    USE SIGNAL ;
    PORT
      LAYER M5 ;
        RECT  26.544 30.132 26.568 30.216 ;
    END
  END b[97]
  PIN b[98]
    DIRECTION OUTPUT ;
    USE SIGNAL ;
    PORT
      LAYER M5 ;
        RECT  26.64 30.132 26.664 30.216 ;
    END
  END b[98]
  PIN b[99]
    DIRECTION OUTPUT ;
    USE SIGNAL ;
    PORT
      LAYER M5 ;
        RECT  26.736 30.132 26.76 30.216 ;
    END
  END b[99]
  PIN b[9]
    DIRECTION OUTPUT ;
    USE SIGNAL ;
    PORT
      LAYER M5 ;
        RECT  30.384 30.132 30.408 30.216 ;
    END
  END b[9]
  PIN ck
    DIRECTION INPUT ;
    USE SIGNAL ;
    PORT
      LAYER M4 ;
        RECT  0 14.832 0.084 14.856 ;
    END
  END ck
  PIN ck_o
    DIRECTION OUTPUT ;
    USE SIGNAL ;
    PORT
      LAYER M4 ;
        RECT  0 14.928 0.084 14.952 ;
    END
  END ck_o
  PIN eb
    DIRECTION OUTPUT ;
    USE SIGNAL ;
    PORT
      LAYER M5 ;
        RECT  26.352 30.132 26.376 30.216 ;
    END
  END eb
  PIN en
    DIRECTION INPUT ;
    USE SIGNAL ;
    PORT
      LAYER M4 ;
        RECT  0 15.024 0.084 15.048 ;
    END
  END en
  PIN VDD
    DIRECTION INOUT ;
    USE POWER ;
    PORT
      LAYER M5 ;
        RECT  61.992 2.151 62.112 27.833 ;
        RECT  59.292 2.151 59.412 27.833 ;
        RECT  56.592 2.151 56.712 27.833 ;
        RECT  53.892 2.151 54.012 27.833 ;
        RECT  51.192 2.151 51.312 27.833 ;
        RECT  48.492 2.151 48.612 27.833 ;
        RECT  45.792 2.151 45.912 27.833 ;
        RECT  43.092 2.151 43.212 27.833 ;
        RECT  40.392 2.151 40.512 27.833 ;
        RECT  37.692 2.151 37.812 27.833 ;
        RECT  34.992 2.151 35.112 27.833 ;
        RECT  32.292 2.151 32.412 27.833 ;
        RECT  29.592 2.151 29.712 27.833 ;
        RECT  26.892 2.151 27.012 27.833 ;
        RECT  24.192 2.151 24.312 27.833 ;
        RECT  21.492 2.151 21.612 27.833 ;
        RECT  18.792 2.151 18.912 27.833 ;
        RECT  16.092 2.151 16.212 27.833 ;
        RECT  13.392 2.151 13.512 27.833 ;
        RECT  10.692 2.151 10.812 27.833 ;
        RECT  7.992 2.151 8.112 27.833 ;
        RECT  5.292 2.151 5.412 27.833 ;
        RECT  2.592 2.151 2.712 27.833 ;
    END
  END VDD
  PIN VSS
    DIRECTION INOUT ;
    USE GROUND ;
    PORT
      LAYER M5 ;
        RECT  61.8 2.137 61.92 27.819 ;
        RECT  59.1 2.137 59.22 27.819 ;
        RECT  56.4 2.137 56.52 27.819 ;
        RECT  53.7 2.137 53.82 27.819 ;
        RECT  51 2.137 51.12 27.819 ;
        RECT  48.3 2.137 48.42 27.819 ;
        RECT  45.6 2.137 45.72 27.819 ;
        RECT  42.9 2.137 43.02 27.819 ;
        RECT  40.2 2.137 40.32 27.819 ;
        RECT  37.5 2.137 37.62 27.819 ;
        RECT  34.8 2.137 34.92 27.819 ;
        RECT  32.1 2.137 32.22 27.819 ;
        RECT  29.4 2.137 29.52 27.819 ;
        RECT  26.7 2.137 26.82 27.819 ;
        RECT  24 2.137 24.12 27.819 ;
        RECT  21.3 2.137 21.42 27.819 ;
        RECT  18.6 2.137 18.72 27.819 ;
        RECT  15.9 2.137 16.02 27.819 ;
        RECT  13.2 2.137 13.32 27.819 ;
        RECT  10.5 2.137 10.62 27.819 ;
        RECT  7.8 2.137 7.92 27.819 ;
        RECT  5.1 2.137 5.22 27.819 ;
        RECT  2.4 2.137 2.52 27.819 ;
    END
  END VSS
  # OT_OBS_CLOSED layer=M5 d_um=1.536 added=27
  OBS
    LAYER RVTN ;
     RECT  2.16 2.16 62.586 2.295 ;
     RECT  2.16 2.565 62.586 2.835 ;
     RECT  2.16 3.105 62.586 3.375 ;
     RECT  2.16 3.645 62.586 3.915 ;
     RECT  2.16 4.185 62.586 4.455 ;
     RECT  2.16 4.725 62.586 4.995 ;
     RECT  2.16 5.265 62.586 5.535 ;
     RECT  2.16 5.805 62.586 6.075 ;
     RECT  2.16 6.345 62.586 6.615 ;
     RECT  2.16 6.885 62.586 7.155 ;
     RECT  2.16 7.425 62.586 7.695 ;
     RECT  2.16 7.965 62.586 8.235 ;
     RECT  2.16 8.505 62.586 8.775 ;
     RECT  2.16 9.045 62.586 9.315 ;
     RECT  2.16 9.585 62.586 9.855 ;
     RECT  2.16 10.125 62.586 10.395 ;
     RECT  2.16 10.665 62.586 10.935 ;
     RECT  2.16 11.205 62.586 11.475 ;
     RECT  2.16 11.745 62.586 12.015 ;
     RECT  2.16 12.285 62.586 12.555 ;
     RECT  2.16 12.825 62.586 13.095 ;
     RECT  2.16 13.365 62.586 13.635 ;
     RECT  2.16 13.905 62.586 14.175 ;
     RECT  2.16 14.445 62.586 14.715 ;
     RECT  2.16 14.985 62.586 15.255 ;
     RECT  2.16 15.525 62.586 15.795 ;
     RECT  2.16 16.065 62.586 16.335 ;
     RECT  2.16 16.605 62.586 16.875 ;
     RECT  2.16 17.145 62.586 17.415 ;
     RECT  2.16 17.685 62.586 17.955 ;
     RECT  2.16 18.225 62.586 18.495 ;
     RECT  2.16 18.765 62.586 19.035 ;
     RECT  2.16 19.305 62.586 19.575 ;
     RECT  2.16 19.845 62.586 20.115 ;
     RECT  2.16 20.385 62.586 20.655 ;
     RECT  2.16 20.925 62.586 21.195 ;
     RECT  2.16 21.465 62.586 21.735 ;
     RECT  2.16 22.005 62.586 22.275 ;
     RECT  2.16 22.545 62.586 22.815 ;
     RECT  2.16 23.085 62.586 23.355 ;
     RECT  2.16 23.625 62.586 23.895 ;
     RECT  2.16 24.165 62.586 24.435 ;
     RECT  2.16 24.705 62.586 24.975 ;
     RECT  2.16 25.245 62.586 25.515 ;
     RECT  2.16 25.785 62.586 26.055 ;
     RECT  2.16 26.325 62.586 26.595 ;
     RECT  2.16 26.865 62.586 27.135 ;
     RECT  2.16 27.405 62.586 27.675 ;
    LAYER RVTP ;
     RECT  2.16 2.295 62.586 2.565 ;
     RECT  2.16 2.835 62.586 3.105 ;
     RECT  2.16 3.375 62.586 3.645 ;
     RECT  2.16 3.915 62.586 4.185 ;
     RECT  2.16 4.455 62.586 4.725 ;
     RECT  2.16 4.995 62.586 5.265 ;
     RECT  2.16 5.535 62.586 5.805 ;
     RECT  2.16 6.075 62.586 6.345 ;
     RECT  2.16 6.615 62.586 6.885 ;
     RECT  2.16 7.155 62.586 7.425 ;
     RECT  2.16 7.695 62.586 7.965 ;
     RECT  2.16 8.235 62.586 8.505 ;
     RECT  2.16 8.775 62.586 9.045 ;
     RECT  2.16 9.315 62.586 9.585 ;
     RECT  2.16 9.855 62.586 10.125 ;
     RECT  2.16 10.395 62.586 10.665 ;
     RECT  2.16 10.935 62.586 11.205 ;
     RECT  2.16 11.475 62.586 11.745 ;
     RECT  2.16 12.015 62.586 12.285 ;
     RECT  2.16 12.555 62.586 12.825 ;
     RECT  2.16 13.095 62.586 13.365 ;
     RECT  2.16 13.635 62.586 13.905 ;
     RECT  2.16 14.175 62.586 14.445 ;
     RECT  2.16 14.715 62.586 14.985 ;
     RECT  2.16 15.255 62.586 15.525 ;
     RECT  2.16 15.795 62.586 16.065 ;
     RECT  2.16 16.335 62.586 16.605 ;
     RECT  2.16 16.875 62.586 17.145 ;
     RECT  2.16 17.415 62.586 17.685 ;
     RECT  2.16 17.955 62.586 18.225 ;
     RECT  2.16 18.495 62.586 18.765 ;
     RECT  2.16 19.035 62.586 19.305 ;
     RECT  2.16 19.575 62.586 19.845 ;
     RECT  2.16 20.115 62.586 20.385 ;
     RECT  2.16 20.655 62.586 20.925 ;
     RECT  2.16 21.195 62.586 21.465 ;
     RECT  2.16 21.735 62.586 22.005 ;
     RECT  2.16 22.275 62.586 22.545 ;
     RECT  2.16 22.815 62.586 23.085 ;
     RECT  2.16 23.355 62.586 23.625 ;
     RECT  2.16 23.895 62.586 24.165 ;
     RECT  2.16 24.435 62.586 24.705 ;
     RECT  2.16 24.975 62.586 25.245 ;
     RECT  2.16 25.515 62.586 25.785 ;
     RECT  2.16 26.055 62.586 26.325 ;
     RECT  2.16 26.595 62.586 26.865 ;
     RECT  2.16 27.135 62.586 27.405 ;
     RECT  2.16 27.675 62.586 27.81 ;
    LAYER M1 ;
     RECT  2.16 2.151 62.586 27.819 ;
    LAYER M2 ;
     RECT  2.16 2.151 33.007 27.819 ;
     RECT  33.007 2.151 33.755 27.864 ;
     RECT  33.755 2.151 62.586 27.819 ;
     RECT  62.586 6.822 63.311 19.404 ;
     RECT  63.311 6.822 63.347 18.864 ;
     RECT  63.347 6.822 63.887 10.89 ;
     RECT  63.347 11.646 63.887 18.864 ;
     RECT  63.887 7.47 63.923 8.19 ;
     RECT  63.887 9.63 63.923 10.584 ;
     RECT  63.887 13.374 63.923 15.552 ;
     RECT  63.887 16.686 63.923 17.442 ;
     RECT  63.887 18.774 63.923 18.792 ;
     RECT  63.923 7.47 63.959 7.488 ;
     RECT  63.923 9.828 63.959 10.386 ;
     RECT  63.923 13.374 63.959 13.734 ;
     RECT  63.923 14.796 63.959 14.814 ;
     RECT  64.651 9.486 64.751 9.504 ;
     RECT  64.651 15.876 64.751 15.894 ;
     RECT  64.651 16.776 64.751 17.829 ;
    LAYER M3 ;
     RECT  2.415 2.143 2.505 2.413 ;
     RECT  5.115 2.143 5.205 2.413 ;
     RECT  7.815 2.143 7.905 2.413 ;
     RECT  10.515 2.143 10.605 2.413 ;
     RECT  13.215 2.143 13.305 2.413 ;
     RECT  15.915 2.143 16.005 2.413 ;
     RECT  18.615 2.143 18.705 2.413 ;
     RECT  21.315 2.143 21.405 2.413 ;
     RECT  24.015 2.143 24.105 2.413 ;
     RECT  26.715 2.143 26.805 2.413 ;
     RECT  29.415 2.143 29.505 2.413 ;
     RECT  32.115 2.143 32.205 2.413 ;
     RECT  34.815 2.143 34.905 2.413 ;
     RECT  37.515 2.143 37.605 2.413 ;
     RECT  40.215 2.143 40.305 2.413 ;
     RECT  42.915 2.143 43.005 2.413 ;
     RECT  45.615 2.143 45.705 2.413 ;
     RECT  48.315 2.143 48.405 2.413 ;
     RECT  51.015 2.143 51.105 2.413 ;
     RECT  53.715 2.143 53.805 2.413 ;
     RECT  56.415 2.143 56.505 2.413 ;
     RECT  59.115 2.143 59.205 2.413 ;
     RECT  61.815 2.143 61.905 2.413 ;
     RECT  56.415 2.413 56.697 6.853 ;
     RECT  59.115 2.413 59.397 6.853 ;
     RECT  60.516 6.781 60.534 6.853 ;
     RECT  60.444 6.853 60.534 6.889 ;
     RECT  56.415 6.853 56.898 6.925 ;
     RECT  60.444 6.889 60.93 6.925 ;
     RECT  61.815 2.413 62.097 6.925 ;
     RECT  54.756 6.889 54.774 6.961 ;
     RECT  60.444 6.925 62.766 6.961 ;
     RECT  63.864 6.817 63.882 6.961 ;
     RECT  34.815 2.413 35.097 7.051 ;
     RECT  58.608 6.853 59.397 7.051 ;
     RECT  60.444 6.961 63.882 7.051 ;
     RECT  56.376 6.925 56.898 7.087 ;
     RECT  57.672 6.961 57.762 7.087 ;
     RECT  54.72 6.961 54.774 7.151 ;
     RECT  56.376 7.087 57.762 7.159 ;
     RECT  55.8 7.159 57.762 7.195 ;
     RECT  58.572 7.051 63.882 7.195 ;
     RECT  34.488 7.051 35.097 7.231 ;
     RECT  55.8 7.195 63.882 7.349 ;
     RECT  55.656 7.357 55.674 7.421 ;
     RECT  56.415 7.349 63.882 7.421 ;
     RECT  34.128 7.231 35.097 7.429 ;
     RECT  48.315 2.413 48.597 7.465 ;
     RECT  58.536 7.421 63.882 7.465 ;
     RECT  40.215 2.413 40.497 7.501 ;
     RECT  40.215 7.501 40.77 7.591 ;
     RECT  47.772 7.465 48.597 7.619 ;
     RECT  33.768 7.429 35.097 7.627 ;
     RECT  42.915 2.413 43.197 7.627 ;
     RECT  40.215 7.591 40.842 7.691 ;
     RECT  58.536 7.465 63.954 7.727 ;
     RECT  63.828 7.727 63.954 7.757 ;
     RECT  42.768 7.627 43.197 7.799 ;
     RECT  54.72 7.151 54.738 7.969 ;
     RECT  54.72 7.969 54.918 8.069 ;
     RECT  54.792 8.069 54.918 8.131 ;
     RECT  63.864 7.757 63.954 8.141 ;
     RECT  51.015 2.413 51.297 8.167 ;
     RECT  33.336 7.627 35.097 8.203 ;
     RECT  56.415 7.421 57.762 8.203 ;
     RECT  58.536 7.727 62.766 8.203 ;
     RECT  50.724 8.167 51.297 8.267 ;
     RECT  54.792 8.131 54.99 8.267 ;
     RECT  55.548 8.275 55.566 8.333 ;
     RECT  56.415 8.203 62.766 8.401 ;
     RECT  55.656 8.401 62.766 8.491 ;
     RECT  63.864 8.141 63.918 8.491 ;
     RECT  33.336 8.203 35.226 8.743 ;
     RECT  33.336 8.743 35.298 8.851 ;
     RECT  53.715 2.413 53.997 9.283 ;
     RECT  54.792 8.267 54.81 9.349 ;
     RECT  55.656 8.491 63.918 9.349 ;
     RECT  51.015 8.267 51.297 9.355 ;
     RECT  54.792 9.349 63.918 9.389 ;
     RECT  64.656 9.451 64.674 9.481 ;
     RECT  50.724 9.355 51.297 9.509 ;
     RECT  64.656 9.481 64.746 9.509 ;
     RECT  64.728 9.509 64.746 9.533 ;
     RECT  45.615 2.413 45.897 9.625 ;
     RECT  55.8 9.389 63.918 9.643 ;
     RECT  33.336 8.851 35.802 9.751 ;
     RECT  38.736 9.751 38.754 9.887 ;
     RECT  33.336 9.751 36.306 10.129 ;
     RECT  55.8 9.643 63.954 10.193 ;
     RECT  33.336 10.129 36.558 10.201 ;
     RECT  54.792 9.389 54.81 10.267 ;
     RECT  55.8 10.193 57.87 10.267 ;
     RECT  54.792 10.267 57.87 10.363 ;
     RECT  58.716 10.193 63.954 10.445 ;
     RECT  33.336 10.201 36.63 10.463 ;
     RECT  29.415 2.413 29.697 10.471 ;
     RECT  58.716 10.445 63.918 10.589 ;
     RECT  29.415 10.471 30.222 10.669 ;
     RECT  30.96 10.435 30.978 10.669 ;
     RECT  32.115 2.413 32.397 10.669 ;
     RECT  29.415 10.669 30.978 11.011 ;
     RECT  32.115 10.669 32.49 11.011 ;
     RECT  54.72 10.363 57.87 11.101 ;
     RECT  58.716 10.589 63.882 11.101 ;
     RECT  29.415 11.011 32.49 11.281 ;
     RECT  38.772 10.843 38.79 11.309 ;
     RECT  46.764 10.843 46.782 11.309 ;
     RECT  29.415 11.281 32.562 11.443 ;
     RECT  33.336 10.463 35.91 11.443 ;
     RECT  37.515 2.413 37.797 11.551 ;
     RECT  41.832 11.551 41.85 11.641 ;
     RECT  41.832 11.641 41.922 11.669 ;
     RECT  40.215 7.691 40.497 11.713 ;
     RECT  41.904 11.669 41.922 11.741 ;
     RECT  54.72 11.101 63.882 11.849 ;
     RECT  40.215 11.713 41.022 12.245 ;
     RECT  40.215 12.245 40.554 12.479 ;
     RECT  29.415 11.443 35.91 12.631 ;
     RECT  63.864 11.849 63.882 12.715 ;
     RECT  54.72 11.849 60.21 12.721 ;
     RECT  61.2 11.849 62.766 12.721 ;
     RECT  52.2 12.571 52.218 12.749 ;
     RECT  63.828 12.715 63.882 12.785 ;
     RECT  53.388 9.283 53.997 12.793 ;
     RECT  54.72 12.721 62.766 12.793 ;
     RECT  45.576 9.625 45.897 12.811 ;
     RECT  45.576 12.811 46.242 12.859 ;
     RECT  29.415 12.631 36.378 12.901 ;
     RECT  29.415 12.901 36.45 12.991 ;
     RECT  45.576 12.859 46.962 13.037 ;
     RECT  53.388 12.793 62.766 13.085 ;
     RECT  53.388 13.085 60.354 13.163 ;
     RECT  63.864 12.785 63.882 13.195 ;
     RECT  61.128 13.085 62.766 13.199 ;
     RECT  45.576 13.037 46.89 13.261 ;
     RECT  51.015 9.509 51.297 13.291 ;
     RECT  44.964 13.261 46.89 13.333 ;
     RECT  29.415 12.991 36.522 13.387 ;
     RECT  37.296 11.551 37.797 13.387 ;
     RECT  38.772 12.859 38.79 13.387 ;
     RECT  29.088 13.387 36.522 13.441 ;
     RECT  37.296 13.387 37.818 13.441 ;
     RECT  38.772 13.387 38.898 13.441 ;
     RECT  5.115 2.413 5.397 13.531 ;
     RECT  13.215 2.413 13.497 13.531 ;
     RECT  21.315 2.413 21.597 13.531 ;
     RECT  26.715 2.413 26.997 13.531 ;
     RECT  44.532 13.333 46.89 13.559 ;
     RECT  44.964 13.559 46.89 13.565 ;
     RECT  5.004 13.531 5.397 13.568 ;
     RECT  13.104 13.531 13.497 13.568 ;
     RECT  21.204 13.531 21.597 13.568 ;
     RECT  53.715 13.163 60.354 13.595 ;
     RECT  50.724 13.291 51.297 13.613 ;
     RECT  29.088 13.441 38.898 13.631 ;
     RECT  6.84 13.531 6.858 13.661 ;
     RECT  14.832 13.531 14.85 13.661 ;
     RECT  26.676 13.531 26.997 13.661 ;
     RECT  29.088 13.631 35.91 13.661 ;
     RECT  53.715 13.595 55.314 13.661 ;
     RECT  36.648 13.631 38.898 13.675 ;
     RECT  54.72 13.661 55.314 13.703 ;
     RECT  36.648 13.675 39.366 13.711 ;
     RECT  63.864 13.195 63.954 13.771 ;
     RECT  56.16 13.595 60.354 13.819 ;
     RECT  61.128 13.199 62.226 13.819 ;
     RECT  45.108 13.565 46.242 13.829 ;
     RECT  45.108 13.829 45.897 13.901 ;
     RECT  56.16 13.819 62.226 13.963 ;
     RECT  63.288 13.771 63.954 13.963 ;
     RECT  36.648 13.711 39.402 13.981 ;
     RECT  40.215 12.479 40.497 13.981 ;
     RECT  42.915 7.799 43.197 13.981 ;
     RECT  56.16 13.963 63.954 14.207 ;
     RECT  45.468 13.901 45.897 14.237 ;
     RECT  42.408 13.981 43.197 14.243 ;
     RECT  36.648 13.981 40.497 14.251 ;
     RECT  41.436 14.143 41.454 14.251 ;
     RECT  29.415 13.661 35.91 14.285 ;
     RECT  36.648 14.251 41.526 14.341 ;
     RECT  36.648 14.341 41.598 14.377 ;
     RECT  51.015 13.613 51.297 14.413 ;
     RECT  36.648 14.377 41.67 14.513 ;
     RECT  50.796 14.413 51.297 14.549 ;
     RECT  2.415 2.413 2.697 14.611 ;
     RECT  56.16 14.207 62.097 14.647 ;
     RECT  36.648 14.513 41.598 14.675 ;
     RECT  2.415 14.611 2.79 14.731 ;
     RECT  54.72 13.703 54.846 14.755 ;
     RECT  55.62 14.647 62.097 14.755 ;
     RECT  29.415 14.285 35.838 14.813 ;
     RECT  2.415 14.731 2.934 14.819 ;
     RECT  63.18 14.207 63.954 14.828 ;
     RECT  2.415 14.819 2.697 15.016 ;
     RECT  53.715 13.661 53.997 15.025 ;
     RECT  54.72 14.755 62.097 15.025 ;
     RECT  2.34 15.016 2.697 15.053 ;
     RECT  53.715 15.025 62.097 15.115 ;
     RECT  63.18 14.828 63.918 15.115 ;
     RECT  36.756 14.675 40.878 15.421 ;
     RECT  53.715 15.115 63.918 15.449 ;
     RECT  42.915 14.243 43.197 15.493 ;
     RECT  36.756 15.421 40.95 15.529 ;
     RECT  53.715 15.449 55.35 15.529 ;
     RECT  53.424 15.529 55.35 15.557 ;
     RECT  36.756 15.529 41.526 15.565 ;
     RECT  56.088 15.449 63.918 15.593 ;
     RECT  56.088 15.593 62.73 15.629 ;
     RECT  36.756 15.565 41.67 15.755 ;
     RECT  53.424 15.557 53.997 15.755 ;
     RECT  53.64 15.755 53.997 15.821 ;
     RECT  36.756 15.755 41.454 15.863 ;
     RECT  64.728 15.835 64.746 15.871 ;
     RECT  64.656 15.871 64.746 15.899 ;
     RECT  64.656 15.899 64.674 15.917 ;
     RECT  29.415 14.813 35.802 15.965 ;
     RECT  42.804 15.493 43.197 15.997 ;
     RECT  56.196 15.629 62.73 16.061 ;
     RECT  42.66 15.997 43.197 16.097 ;
     RECT  46.764 15.691 46.782 16.157 ;
     RECT  56.304 16.061 62.73 16.363 ;
     RECT  51.015 14.549 51.297 16.375 ;
     RECT  54.72 15.557 55.35 16.673 ;
     RECT  29.415 15.965 30.438 16.681 ;
     RECT  54.792 16.673 55.35 16.771 ;
     RECT  64.656 16.747 64.674 16.771 ;
     RECT  29.268 16.681 30.438 16.807 ;
     RECT  54.792 16.771 55.53 16.807 ;
     RECT  56.304 16.363 62.838 16.807 ;
     RECT  42.732 16.097 43.197 16.843 ;
     RECT  42.66 16.843 43.197 16.943 ;
     RECT  26.715 13.661 26.997 16.951 ;
     RECT  27.9 16.573 27.918 16.951 ;
     RECT  31.176 15.965 35.802 17.041 ;
     RECT  48.315 7.619 48.597 17.041 ;
     RECT  54.792 16.807 62.838 17.041 ;
     RECT  63.828 15.593 63.918 17.041 ;
     RECT  47.844 17.041 48.597 17.077 ;
     RECT  50.724 16.375 51.297 17.105 ;
     RECT  47.592 17.077 48.597 17.117 ;
     RECT  31.176 17.041 35.874 17.141 ;
     RECT  26.715 16.951 27.918 17.149 ;
     RECT  28.764 16.807 30.438 17.149 ;
     RECT  54.792 17.041 63.918 17.177 ;
     RECT  36.756 15.863 41.022 17.213 ;
     RECT  26.715 17.149 30.438 17.323 ;
     RECT  31.176 17.141 35.766 17.323 ;
     RECT  47.844 17.117 48.597 17.339 ;
     RECT  54.792 17.177 62.118 17.339 ;
     RECT  63.288 17.177 63.918 17.447 ;
     RECT  26.715 17.323 35.766 17.453 ;
     RECT  25.668 14.881 25.686 17.455 ;
     RECT  26.715 17.453 35.694 17.455 ;
     RECT  25.668 17.455 35.694 17.483 ;
     RECT  63.288 17.447 63.882 17.681 ;
     RECT  54.792 17.339 60.498 17.725 ;
     RECT  64.656 16.771 64.746 17.837 ;
     RECT  64.728 17.837 64.746 17.885 ;
     RECT  61.38 17.339 62.118 17.899 ;
     RECT  36.756 17.213 40.497 18.029 ;
     RECT  39.672 18.029 40.497 18.125 ;
     RECT  63.864 17.681 63.882 18.187 ;
     RECT  54.72 17.725 60.498 18.221 ;
     RECT  56.16 18.221 60.498 18.265 ;
     RECT  56.16 18.265 60.642 18.301 ;
     RECT  61.38 17.899 62.73 18.301 ;
     RECT  26.1 17.483 35.694 18.317 ;
     RECT  56.16 18.301 62.73 18.562 ;
     RECT  54.72 18.221 55.386 18.599 ;
     RECT  56.16 18.562 62.766 18.599 ;
     RECT  54.792 18.599 55.386 18.689 ;
     RECT  48.315 17.339 48.597 18.715 ;
     RECT  45.576 14.237 45.897 18.733 ;
     RECT  54.792 18.689 55.242 18.749 ;
     RECT  26.1 18.317 27.306 18.797 ;
     RECT  54.792 18.749 54.81 18.797 ;
     RECT  63.864 18.187 63.918 18.802 ;
     RECT  63.864 18.802 63.882 18.805 ;
     RECT  47.916 18.715 48.597 18.841 ;
     RECT  58.68 18.599 62.766 18.859 ;
     RECT  63.828 18.805 63.882 18.859 ;
     RECT  58.68 18.859 63.882 18.869 ;
     RECT  47.808 18.841 48.597 18.893 ;
     RECT  46.8 18.811 46.818 18.959 ;
     RECT  47.88 18.893 48.597 18.959 ;
     RECT  58.68 18.869 63.846 18.989 ;
     RECT  58.68 18.989 63.306 18.995 ;
     RECT  58.68 18.995 60.534 19.085 ;
     RECT  61.776 18.995 63.306 19.103 ;
     RECT  56.16 18.599 57.942 19.139 ;
     RECT  61.815 19.103 63.306 19.229 ;
     RECT  56.415 19.139 57.942 19.277 ;
     RECT  56.415 19.277 57.618 19.337 ;
     RECT  57.564 19.337 57.618 19.373 ;
     RECT  58.68 19.085 60.426 19.409 ;
     RECT  63.288 19.229 63.306 19.409 ;
     RECT  57.564 19.373 57.582 19.499 ;
     RECT  59.115 19.409 60.426 19.643 ;
     RECT  28.044 18.317 35.694 19.949 ;
     RECT  36.756 18.029 38.754 20.525 ;
     RECT  28.044 19.949 32.397 21.053 ;
     RECT  45.504 18.733 45.897 21.115 ;
     RECT  31.176 21.053 32.397 21.581 ;
     RECT  44.964 21.115 46.098 21.659 ;
     RECT  28.044 21.053 30.438 21.677 ;
     RECT  39.708 18.125 40.497 21.677 ;
     RECT  49.32 7.123 49.338 23.279 ;
     RECT  48.315 18.959 48.597 23.323 ;
     RECT  28.476 21.677 30.438 23.791 ;
     RECT  28.476 23.791 30.51 23.927 ;
     RECT  28.476 23.927 30.15 24.461 ;
     RECT  28.476 24.461 28.494 24.509 ;
     RECT  36.756 20.525 38.718 25.037 ;
     RECT  38.7 25.037 38.718 25.085 ;
     RECT  31.356 21.581 32.397 26.237 ;
     RECT  45.504 21.659 45.897 26.285 ;
     RECT  42.915 16.943 43.197 26.401 ;
     RECT  26.1 18.797 27.09 26.527 ;
     RECT  25.128 26.587 25.146 26.627 ;
     RECT  26.028 26.527 27.09 26.663 ;
     RECT  25.308 26.671 25.326 26.789 ;
     RECT  26.316 26.663 27.09 26.789 ;
     RECT  31.392 26.237 32.397 27.211 ;
     RECT  33.264 19.949 35.694 27.211 ;
     RECT  48.315 23.323 48.726 27.473 ;
     RECT  36.756 25.037 37.797 27.509 ;
     RECT  2.415 15.053 2.697 27.557 ;
     RECT  5.115 13.568 5.397 27.557 ;
     RECT  7.815 2.413 8.097 27.557 ;
     RECT  10.515 2.413 10.797 27.557 ;
     RECT  13.215 13.568 13.497 27.557 ;
     RECT  15.915 2.413 16.197 27.557 ;
     RECT  18.615 2.413 18.897 27.557 ;
     RECT  21.315 13.568 21.597 27.557 ;
     RECT  24.015 2.413 24.297 27.557 ;
     RECT  37.515 27.509 37.797 27.557 ;
     RECT  40.215 21.677 40.497 27.557 ;
     RECT  42.915 26.401 43.614 27.557 ;
     RECT  45.615 26.285 45.897 27.557 ;
     RECT  48.315 27.473 48.597 27.557 ;
     RECT  51.015 17.105 51.297 27.557 ;
     RECT  53.715 15.821 53.997 27.557 ;
     RECT  56.415 19.337 56.697 27.557 ;
     RECT  59.115 19.643 60.03 27.557 ;
     RECT  61.815 19.229 62.097 27.557 ;
     RECT  59.307 27.557 60.03 27.635 ;
     RECT  26.496 26.789 27.09 27.751 ;
     RECT  29.34 24.461 30.15 27.751 ;
     RECT  31.392 27.211 35.694 27.751 ;
     RECT  2.607 27.557 2.697 27.827 ;
     RECT  5.307 27.557 5.397 27.827 ;
     RECT  8.007 27.557 8.097 27.827 ;
     RECT  10.707 27.557 10.797 27.827 ;
     RECT  13.407 27.557 13.497 27.827 ;
     RECT  16.107 27.557 16.197 27.827 ;
     RECT  18.807 27.557 18.897 27.827 ;
     RECT  21.507 27.557 21.597 27.827 ;
     RECT  24.207 27.557 24.297 27.827 ;
     RECT  37.707 27.557 37.797 27.827 ;
     RECT  40.407 27.557 40.497 27.827 ;
     RECT  43.107 27.557 43.614 27.827 ;
     RECT  45.807 27.557 45.897 27.827 ;
     RECT  48.507 27.557 48.597 27.827 ;
     RECT  51.207 27.557 51.297 27.827 ;
     RECT  53.907 27.557 53.997 27.827 ;
     RECT  56.607 27.557 56.697 27.827 ;
     RECT  59.307 27.635 59.397 27.827 ;
     RECT  62.007 27.557 62.097 27.827 ;
     RECT  29.34 27.751 35.694 27.869 ;
     RECT  36.756 27.509 36.774 27.869 ;
     RECT  29.556 27.869 35.19 27.917 ;
     RECT  52.992 27.751 53.01 27.917 ;
     RECT  26.46 27.751 27.09 27.965 ;
     RECT  29.556 27.917 30.762 27.965 ;
     RECT  43.596 27.827 43.614 28.205 ;
     RECT  29.556 27.965 30.15 28.493 ;
     RECT  31.5 27.917 35.19 28.493 ;
     RECT  26.46 27.965 26.478 29.069 ;
     RECT  31.572 28.493 32.67 29.069 ;
     RECT  35.172 28.493 35.19 29.069 ;
     RECT  31.572 29.069 32.022 29.357 ;
     RECT  34.416 28.493 34.434 29.645 ;
     RECT  27.216 29.899 27.234 29.947 ;
     RECT  35.208 29.659 35.226 29.995 ;
     RECT  27.108 29.947 27.234 30.077 ;
     RECT  35.208 29.995 35.298 30.077 ;
     RECT  27.108 30.077 27.126 30.125 ;
     RECT  30.132 28.493 30.15 30.125 ;
     RECT  32.004 29.357 32.022 30.125 ;
     RECT  35.28 30.077 35.298 30.125 ;
    LAYER M4 ;
     RECT  0.084 14.832 0.133 14.856 ;
     RECT  0.06 14.856 0.133 14.928 ;
     RECT  0.084 14.928 0.133 14.952 ;
     RECT  0.06 14.952 0.133 15.024 ;
     RECT  0.084 15.024 0.133 15.048 ;
     RECT  0.133 13.872 2.408 15.048 ;
     RECT  2.408 2.148 2.512 27.552 ;
     RECT  2.512 2.418 2.6 27.552 ;
     RECT  2.6 2.418 2.704 27.822 ;
     RECT  2.704 13.536 2.945 14.76 ;
     RECT  2.945 13.536 5.108 13.896 ;
     RECT  5.108 2.148 5.212 27.552 ;
     RECT  5.212 2.418 5.3 27.552 ;
     RECT  5.3 2.418 5.404 27.822 ;
     RECT  5.404 13.536 7.808 13.896 ;
     RECT  7.808 2.148 7.912 27.552 ;
     RECT  7.912 2.418 8 27.552 ;
     RECT  8 2.418 8.104 27.822 ;
     RECT  8.104 13.632 10.508 13.896 ;
     RECT  10.508 2.148 10.612 27.552 ;
     RECT  10.612 2.418 10.7 27.552 ;
     RECT  10.7 2.418 10.804 27.822 ;
     RECT  10.804 13.536 13.208 13.896 ;
     RECT  13.208 2.148 13.312 27.552 ;
     RECT  13.312 2.418 13.4 27.552 ;
     RECT  13.4 2.418 13.504 27.822 ;
     RECT  13.504 13.536 14.861 13.896 ;
     RECT  14.861 13.632 15.908 13.896 ;
     RECT  15.908 2.148 16.012 27.552 ;
     RECT  16.012 2.418 16.1 27.552 ;
     RECT  16.1 2.418 16.204 27.822 ;
     RECT  16.204 13.632 18.608 13.896 ;
     RECT  18.608 2.148 18.712 27.552 ;
     RECT  18.712 2.418 18.8 27.552 ;
     RECT  18.8 2.418 18.904 27.822 ;
     RECT  18.904 13.536 21.308 13.896 ;
     RECT  21.308 2.148 21.412 27.552 ;
     RECT  21.412 2.418 21.5 27.552 ;
     RECT  21.5 2.418 21.604 27.822 ;
     RECT  21.604 13.536 24.008 13.896 ;
     RECT  24.008 2.148 24.112 27.552 ;
     RECT  24.112 2.418 24.2 27.552 ;
     RECT  24.2 2.418 24.304 27.822 ;
     RECT  26.437 24.432 26.485 24.456 ;
     RECT  26.341 29.04 26.489 29.064 ;
     RECT  26.485 30.048 26.581 30.072 ;
     RECT  24.304 13.632 26.708 13.896 ;
     RECT  26.581 18.528 26.708 18.552 ;
     RECT  26.485 24.096 26.708 24.456 ;
     RECT  24.304 26.592 26.708 26.616 ;
     RECT  26.708 2.148 26.812 27.552 ;
     RECT  26.812 2.418 26.9 27.552 ;
     RECT  26.9 2.418 26.917 27.822 ;
     RECT  26.917 2.418 27.004 27.96 ;
     RECT  26.581 29.808 27.068 30.072 ;
     RECT  27.004 27.936 27.101 27.96 ;
     RECT  27.068 29.808 27.155 30.12 ;
     RECT  27.155 29.808 27.289 30.072 ;
     RECT  27.289 29.808 27.299 29.976 ;
     RECT  27.004 21.648 28.073 21.672 ;
     RECT  27.004 24.096 28.357 24.456 ;
     RECT  28.357 24.096 28.453 24.504 ;
     RECT  28.549 20.592 28.645 20.616 ;
     RECT  28.645 20.544 28.741 20.616 ;
     RECT  27.004 13.632 29.077 13.896 ;
     RECT  27.685 29.328 29.173 29.352 ;
     RECT  27.004 17.664 29.185 19.368 ;
     RECT  28.261 27.888 29.221 27.912 ;
     RECT  28.741 20.544 29.269 21 ;
     RECT  29.173 22.032 29.269 22.056 ;
     RECT  29.077 13.392 29.408 13.896 ;
     RECT  27.004 16.08 29.408 16.104 ;
     RECT  29.185 17.136 29.408 19.368 ;
     RECT  29.269 20.544 29.408 22.056 ;
     RECT  28.453 23.328 29.408 24.504 ;
     RECT  27.004 26.592 29.408 26.616 ;
     RECT  29.221 27.84 29.408 27.912 ;
     RECT  29.408 2.148 29.509 27.912 ;
     RECT  29.509 2.148 29.512 28.2 ;
     RECT  29.512 2.418 29.545 28.2 ;
     RECT  29.173 29.328 29.545 30.072 ;
     RECT  29.545 2.418 29.701 30.072 ;
     RECT  29.701 2.418 29.704 30.12 ;
     RECT  29.704 23.904 29.945 23.928 ;
     RECT  29.704 27.792 30.161 30.12 ;
     RECT  29.704 19.344 30.485 19.368 ;
     RECT  29.704 10.752 30.701 14.232 ;
     RECT  29.704 22.032 30.757 22.056 ;
     RECT  29.704 26.592 30.757 26.616 ;
     RECT  30.161 27.792 30.757 30.072 ;
     RECT  29.704 20.592 30.853 21.048 ;
     RECT  30.757 22.032 30.947 22.824 ;
     RECT  30.853 19.872 30.949 21.048 ;
     RECT  30.947 22.032 30.949 22.728 ;
     RECT  30.949 19.872 31.043 22.728 ;
     RECT  30.757 26.592 31.043 30.072 ;
     RECT  31.043 26.592 31.301 26.616 ;
     RECT  30.701 10.944 31.517 14.232 ;
     RECT  31.043 27.792 31.529 30.072 ;
     RECT  31.529 29.328 31.601 30.072 ;
     RECT  29.704 15.936 31.885 16.104 ;
     RECT  29.704 17.136 31.885 18.216 ;
     RECT  31.601 29.904 31.909 30.072 ;
     RECT  31.909 29.904 32.033 30.12 ;
     RECT  31.517 10.944 32.108 14.808 ;
     RECT  31.885 15.936 32.108 18.792 ;
     RECT  31.043 19.872 32.108 22.056 ;
     RECT  31.301 26.208 32.108 26.616 ;
     RECT  31.529 27.792 32.108 28.2 ;
     RECT  32.033 29.904 32.147 30.024 ;
     RECT  32.108 2.148 32.212 28.2 ;
     RECT  32.212 2.418 32.404 28.2 ;
     RECT  32.404 27.888 32.581 28.2 ;
     RECT  32.581 27.888 32.681 29.064 ;
     RECT  32.404 19.872 33.041 19.944 ;
     RECT  33.041 19.872 33.221 19.896 ;
     RECT  32.404 15.936 33.445 17.64 ;
     RECT  32.404 18.768 33.541 18.792 ;
     RECT  32.404 12.288 33.617 14.808 ;
     RECT  33.541 18.72 33.689 18.792 ;
     RECT  32.404 10.944 33.721 11.208 ;
     RECT  32.404 26.592 33.925 26.616 ;
     RECT  33.925 26.592 34.556 26.76 ;
     RECT  34.213 29.616 34.789 29.64 ;
     RECT  33.721 10.944 34.808 11.256 ;
     RECT  33.617 12.288 34.808 14.04 ;
     RECT  33.445 15.792 34.808 17.64 ;
     RECT  33.689 18.72 34.808 18.744 ;
     RECT  34.501 19.92 34.808 19.944 ;
     RECT  34.556 26.208 34.808 26.76 ;
     RECT  32.681 27.888 34.808 28.488 ;
     RECT  34.808 2.148 34.912 28.488 ;
     RECT  34.789 29.616 34.981 29.832 ;
     RECT  34.912 2.418 35.077 28.488 ;
     RECT  34.981 29.568 35.077 29.832 ;
     RECT  35.077 2.418 35.104 29.832 ;
     RECT  35.104 27.84 35.153 29.832 ;
     RECT  35.153 27.84 35.201 30.072 ;
     RECT  35.201 29.568 35.236 30.072 ;
     RECT  35.236 29.568 35.267 30.12 ;
     RECT  35.267 29.664 35.315 30.12 ;
     RECT  35.104 10.224 35.345 19.368 ;
     RECT  35.104 26.208 35.345 26.616 ;
     RECT  35.315 30 35.353 30.12 ;
     RECT  35.345 10.8 35.363 19.272 ;
     RECT  35.345 26.304 35.363 26.616 ;
     RECT  35.353 30 35.363 30.024 ;
     RECT  35.363 10.8 35.525 18.216 ;
     RECT  35.525 10.944 35.849 18.216 ;
     RECT  35.849 10.944 35.921 14.28 ;
     RECT  35.849 15.456 36.325 18.216 ;
     RECT  37.237 30.048 37.333 30.072 ;
     RECT  37.333 29.952 37.381 30.072 ;
     RECT  35.921 10.944 37.508 11.256 ;
     RECT  35.921 12.336 37.508 14.232 ;
     RECT  36.325 15.456 37.508 18.792 ;
     RECT  36.709 19.92 37.508 19.944 ;
     RECT  35.363 26.592 37.508 26.616 ;
     RECT  35.201 27.84 37.508 28.2 ;
     RECT  37.508 2.148 37.612 28.2 ;
     RECT  37.381 29.856 37.619 30.072 ;
     RECT  37.612 2.418 37.804 28.2 ;
     RECT  37.619 29.952 37.955 30.072 ;
     RECT  37.804 15.456 37.973 18.744 ;
     RECT  37.955 29.952 38.051 30.024 ;
     RECT  38.051 29.952 38.147 29.976 ;
     RECT  37.804 25.008 38.513 25.08 ;
     RECT  37.973 15.456 38.621 18.216 ;
     RECT  38.513 25.056 38.729 25.08 ;
     RECT  37.804 20.496 38.765 20.52 ;
     RECT  37.804 10.848 38.801 11.304 ;
     RECT  38.801 10.944 40.208 11.256 ;
     RECT  37.804 12.336 40.208 13.896 ;
     RECT  38.621 15.456 40.208 18.12 ;
     RECT  37.804 21.648 40.208 21.672 ;
     RECT  37.804 26.592 40.208 26.616 ;
     RECT  37.804 27.888 40.208 28.2 ;
     RECT  40.208 2.148 40.312 28.2 ;
     RECT  40.312 2.418 40.504 28.2 ;
     RECT  40.504 12.336 40.565 13.896 ;
     RECT  40.504 15.744 40.889 16.104 ;
     RECT  40.504 10.944 42.908 11.256 ;
     RECT  40.565 12.864 42.908 13.896 ;
     RECT  40.889 15.792 42.908 16.104 ;
     RECT  40.504 17.136 42.908 17.64 ;
     RECT  40.504 26.592 42.908 26.616 ;
     RECT  40.504 27.888 42.908 28.2 ;
     RECT  42.908 2.148 43.012 28.2 ;
     RECT  43.012 2.418 43.204 28.2 ;
     RECT  43.204 27.888 43.625 28.2 ;
     RECT  43.204 17.136 44.821 17.64 ;
     RECT  43.204 12.864 45.413 13.896 ;
     RECT  43.204 10.944 45.608 11.256 ;
     RECT  45.413 12.864 45.608 14.232 ;
     RECT  43.204 15.792 45.608 16.104 ;
     RECT  44.821 17.088 45.608 17.64 ;
     RECT  44.953 21.12 45.608 21.144 ;
     RECT  43.204 26.592 45.608 26.616 ;
     RECT  43.625 27.888 45.608 27.912 ;
     RECT  45.608 2.148 45.712 27.912 ;
     RECT  45.712 2.418 45.904 27.912 ;
     RECT  45.904 15.696 46.115 17.448 ;
     RECT  45.904 21.12 46.153 21.144 ;
     RECT  45.904 10.848 46.793 11.304 ;
     RECT  46.115 15.696 46.793 17.16 ;
     RECT  45.904 18.816 47.797 18.84 ;
     RECT  47.797 18.816 47.893 18.888 ;
     RECT  47.893 18.768 47.905 18.888 ;
     RECT  46.793 10.944 48.308 11.256 ;
     RECT  45.904 12.576 48.308 13.656 ;
     RECT  46.793 15.792 48.308 17.16 ;
     RECT  47.905 18.72 48.308 18.888 ;
     RECT  45.904 26.592 48.308 26.616 ;
     RECT  45.904 27.888 48.308 27.912 ;
     RECT  48.308 2.148 48.412 27.912 ;
     RECT  48.412 2.418 48.604 27.912 ;
     RECT  48.604 10.944 51.008 11.256 ;
     RECT  48.604 12.576 51.008 13.656 ;
     RECT  48.604 15.792 51.008 17.16 ;
     RECT  48.604 18.72 51.008 18.744 ;
     RECT  48.604 27.888 51.008 27.912 ;
     RECT  51.008 2.148 51.112 27.912 ;
     RECT  51.112 2.418 51.304 27.912 ;
     RECT  51.304 12.576 52.229 13.656 ;
     RECT  51.304 27.888 53.021 27.912 ;
     RECT  51.304 10.944 53.708 11.256 ;
     RECT  52.229 12.864 53.708 13.656 ;
     RECT  51.304 15.792 53.708 17.16 ;
     RECT  51.304 18.72 53.708 18.744 ;
     RECT  53.708 2.148 53.812 27.822 ;
     RECT  53.812 2.418 54.004 27.822 ;
     RECT  54.004 12.528 54.709 13.656 ;
     RECT  54.709 12.528 54.785 13.608 ;
     RECT  54.004 10.848 55.285 11.304 ;
     RECT  54.004 15.216 55.357 17.16 ;
     RECT  55.285 10.848 55.484 11.544 ;
     RECT  54.785 12.528 55.484 13.416 ;
     RECT  55.465 9.36 55.501 9.384 ;
     RECT  55.484 10.848 55.501 13.416 ;
     RECT  55.537 8.304 55.645 8.328 ;
     RECT  55.357 14.784 56.185 17.16 ;
     RECT  56.185 14.688 56.257 17.16 ;
     RECT  56.257 14.64 56.365 17.16 ;
     RECT  54.004 18.72 56.365 18.744 ;
     RECT  55.645 7.392 56.408 8.328 ;
     RECT  55.501 9.36 56.408 13.416 ;
     RECT  56.365 14.64 56.408 18.744 ;
     RECT  56.408 2.148 56.512 27.552 ;
     RECT  56.512 2.418 56.6 27.552 ;
     RECT  56.6 2.418 56.704 27.822 ;
     RECT  56.704 7.392 56.819 19.176 ;
     RECT  56.819 7.968 57.629 19.176 ;
     RECT  57.629 19.152 57.913 19.176 ;
     RECT  57.629 7.968 58.381 17.928 ;
     RECT  58.381 7.392 58.561 17.928 ;
     RECT  58.561 7.056 58.813 17.928 ;
     RECT  57.913 19.152 58.813 19.272 ;
     RECT  58.813 7.056 59.108 19.32 ;
     RECT  59.108 2.148 59.212 27.552 ;
     RECT  59.212 2.418 59.3 27.552 ;
     RECT  59.3 2.418 59.404 27.822 ;
     RECT  59.404 7.2 60.545 19.08 ;
     RECT  60.545 7.2 61.549 18.792 ;
     RECT  61.549 7.152 61.808 18.792 ;
     RECT  61.808 2.148 61.912 27.552 ;
     RECT  61.912 2.418 62 27.552 ;
     RECT  62 2.418 62.104 27.822 ;
     RECT  62.104 7.152 63.169 13.992 ;
     RECT  62.104 15.12 63.169 19.08 ;
     RECT  63.169 7.152 63.277 19.08 ;
     RECT  63.277 7.056 63.853 19.08 ;
     RECT  63.853 6.864 64.692 6.888 ;
     RECT  63.853 6.888 64.716 6.96 ;
     RECT  63.853 6.96 64.692 6.984 ;
     RECT  63.853 6.984 64.716 7.056 ;
     RECT  63.853 7.056 64.692 7.08 ;
     RECT  63.853 7.08 64.716 7.152 ;
     RECT  63.853 7.152 64.692 7.176 ;
     RECT  63.853 7.176 64.716 7.248 ;
     RECT  63.853 7.248 64.692 7.272 ;
     RECT  63.853 7.272 64.716 7.344 ;
     RECT  63.853 7.344 64.692 7.368 ;
     RECT  63.853 7.368 64.716 7.44 ;
     RECT  63.853 7.44 64.692 7.464 ;
     RECT  63.853 7.464 64.716 7.536 ;
     RECT  63.853 7.536 64.692 7.56 ;
     RECT  63.853 7.56 64.716 7.632 ;
     RECT  63.853 7.632 64.692 7.656 ;
     RECT  63.853 7.656 64.716 7.728 ;
     RECT  63.853 7.728 64.692 7.752 ;
     RECT  63.853 7.752 64.716 7.824 ;
     RECT  63.853 7.824 64.692 7.848 ;
     RECT  63.853 7.848 64.716 7.92 ;
     RECT  63.853 7.92 64.692 7.944 ;
     RECT  63.853 7.944 64.716 8.016 ;
     RECT  63.853 8.016 64.692 8.04 ;
     RECT  63.853 8.04 64.716 8.112 ;
     RECT  63.853 8.112 64.692 8.136 ;
     RECT  63.853 8.136 64.716 8.208 ;
     RECT  63.853 8.208 64.692 8.232 ;
     RECT  63.853 8.232 64.716 8.304 ;
     RECT  63.853 8.304 64.692 8.328 ;
     RECT  63.853 8.328 64.716 8.4 ;
     RECT  63.853 8.4 64.692 8.424 ;
     RECT  63.853 8.424 64.716 8.496 ;
     RECT  63.853 8.496 64.692 8.52 ;
     RECT  63.853 8.52 64.716 8.592 ;
     RECT  63.853 8.592 64.692 8.616 ;
     RECT  63.853 8.616 64.716 8.688 ;
     RECT  63.853 8.688 64.692 8.712 ;
     RECT  63.853 8.712 64.716 8.784 ;
     RECT  63.853 8.784 64.692 8.808 ;
     RECT  63.853 8.808 64.716 8.88 ;
     RECT  63.853 8.88 64.692 8.904 ;
     RECT  63.853 8.904 64.716 8.976 ;
     RECT  63.853 8.976 64.692 9 ;
     RECT  63.853 9 64.716 9.072 ;
     RECT  63.853 9.072 64.692 9.096 ;
     RECT  63.853 9.096 64.716 9.168 ;
     RECT  63.853 9.168 64.692 9.192 ;
     RECT  63.853 9.192 64.716 9.264 ;
     RECT  63.853 9.264 64.692 9.288 ;
     RECT  63.853 9.288 64.716 9.36 ;
     RECT  63.853 9.36 64.692 9.384 ;
     RECT  63.853 9.384 64.716 9.456 ;
     RECT  63.853 9.456 64.692 9.48 ;
     RECT  63.853 9.48 64.716 9.552 ;
     RECT  63.853 9.552 64.692 9.576 ;
     RECT  63.853 9.576 64.716 9.648 ;
     RECT  63.853 9.648 64.692 9.672 ;
     RECT  63.853 9.672 64.716 9.744 ;
     RECT  63.853 9.744 64.692 9.768 ;
     RECT  63.853 9.768 64.716 9.84 ;
     RECT  63.853 9.84 64.692 9.864 ;
     RECT  63.853 9.864 64.716 9.936 ;
     RECT  63.853 9.936 64.692 9.96 ;
     RECT  63.853 9.96 64.716 10.032 ;
     RECT  63.853 10.032 64.692 10.056 ;
     RECT  63.853 10.056 64.716 10.128 ;
     RECT  63.853 10.128 64.692 10.152 ;
     RECT  63.853 10.152 64.716 10.224 ;
     RECT  63.853 10.224 64.692 10.248 ;
     RECT  63.853 10.248 64.716 10.32 ;
     RECT  63.853 10.32 64.692 10.344 ;
     RECT  63.853 10.344 64.716 10.416 ;
     RECT  63.853 10.416 64.692 10.44 ;
     RECT  63.853 10.44 64.716 10.512 ;
     RECT  63.853 10.512 64.692 10.536 ;
     RECT  63.853 10.536 64.716 10.608 ;
     RECT  63.853 10.608 64.692 10.632 ;
     RECT  63.853 10.632 64.716 10.704 ;
     RECT  63.853 10.704 64.692 10.728 ;
     RECT  63.853 10.728 64.716 10.8 ;
     RECT  63.853 10.8 64.692 10.824 ;
     RECT  63.853 10.824 64.716 10.896 ;
     RECT  63.853 10.896 64.692 10.92 ;
     RECT  63.853 10.92 64.716 10.992 ;
     RECT  63.853 10.992 64.692 11.016 ;
     RECT  63.853 11.016 64.716 11.088 ;
     RECT  63.853 11.088 64.692 11.112 ;
     RECT  63.853 11.112 64.716 11.184 ;
     RECT  63.853 11.184 64.692 11.208 ;
     RECT  63.853 11.208 64.716 11.28 ;
     RECT  63.853 11.28 64.692 11.304 ;
     RECT  63.853 11.304 64.716 11.376 ;
     RECT  63.853 11.376 64.692 11.4 ;
     RECT  63.853 11.4 64.716 11.472 ;
     RECT  63.853 11.472 64.692 11.496 ;
     RECT  63.853 11.496 64.716 11.568 ;
     RECT  63.853 11.568 64.692 11.592 ;
     RECT  63.853 11.592 64.716 11.664 ;
     RECT  63.853 11.664 64.692 11.688 ;
     RECT  63.853 11.688 64.716 11.76 ;
     RECT  63.853 11.76 64.692 11.784 ;
     RECT  63.853 11.784 64.716 11.856 ;
     RECT  63.853 11.856 64.692 11.88 ;
     RECT  63.853 11.88 64.716 11.952 ;
     RECT  63.853 11.952 64.692 11.976 ;
     RECT  63.853 11.976 64.716 12.048 ;
     RECT  63.853 12.048 64.692 12.072 ;
     RECT  63.853 12.072 64.716 12.144 ;
     RECT  63.853 12.144 64.692 12.168 ;
     RECT  63.853 12.168 64.716 12.24 ;
     RECT  63.853 12.24 64.692 12.264 ;
     RECT  63.853 12.264 64.716 12.336 ;
     RECT  63.853 12.336 64.692 12.36 ;
     RECT  63.853 12.36 64.716 12.432 ;
     RECT  63.853 12.432 64.692 12.456 ;
     RECT  63.853 12.456 64.716 12.528 ;
     RECT  63.853 12.528 64.692 12.552 ;
     RECT  63.853 12.552 64.716 12.624 ;
     RECT  63.853 12.624 64.692 12.648 ;
     RECT  63.853 12.648 64.716 12.72 ;
     RECT  63.853 12.72 64.692 12.744 ;
     RECT  63.853 12.744 64.716 12.816 ;
     RECT  63.853 12.816 64.692 12.84 ;
     RECT  63.853 12.84 64.716 12.912 ;
     RECT  63.853 12.912 64.692 12.936 ;
     RECT  63.853 12.936 64.716 13.008 ;
     RECT  63.853 13.008 64.692 13.032 ;
     RECT  63.853 13.032 64.716 13.104 ;
     RECT  63.853 13.104 64.692 13.128 ;
     RECT  63.853 13.128 64.716 13.2 ;
     RECT  63.853 13.2 64.692 13.224 ;
     RECT  63.853 13.224 64.716 13.296 ;
     RECT  63.853 13.296 64.692 13.32 ;
     RECT  63.853 13.32 64.716 13.392 ;
     RECT  63.853 13.392 64.692 13.416 ;
     RECT  63.853 13.416 64.716 13.488 ;
     RECT  63.853 13.488 64.692 13.512 ;
     RECT  63.853 13.512 64.716 13.584 ;
     RECT  63.853 13.584 64.692 13.608 ;
     RECT  63.853 13.608 64.716 13.68 ;
     RECT  63.853 13.68 64.692 13.704 ;
     RECT  63.853 13.704 64.716 13.776 ;
     RECT  63.853 13.776 64.692 13.8 ;
     RECT  63.853 13.8 64.716 13.872 ;
     RECT  63.853 13.872 64.692 13.896 ;
     RECT  63.853 13.896 64.716 13.968 ;
     RECT  63.853 13.968 64.692 13.992 ;
     RECT  63.853 13.992 64.716 14.064 ;
     RECT  63.853 14.064 64.692 14.088 ;
     RECT  63.853 14.088 64.716 14.16 ;
     RECT  63.853 14.16 64.692 14.184 ;
     RECT  63.853 14.184 64.716 14.256 ;
     RECT  63.853 14.256 64.692 14.28 ;
     RECT  63.853 14.28 64.716 14.352 ;
     RECT  63.853 14.352 64.692 14.376 ;
     RECT  63.853 14.376 64.716 14.448 ;
     RECT  63.853 14.448 64.692 14.472 ;
     RECT  63.853 14.472 64.716 14.544 ;
     RECT  63.853 14.544 64.692 14.568 ;
     RECT  63.853 14.568 64.716 14.64 ;
     RECT  63.853 14.64 64.692 14.664 ;
     RECT  63.853 14.664 64.716 14.736 ;
     RECT  63.853 14.736 64.692 14.76 ;
     RECT  63.853 14.76 64.716 14.832 ;
     RECT  63.853 14.832 64.692 14.856 ;
     RECT  63.853 14.856 64.716 14.928 ;
     RECT  63.853 14.928 64.692 14.952 ;
     RECT  63.853 14.952 64.716 15.024 ;
     RECT  63.853 15.024 64.692 15.048 ;
     RECT  63.853 15.048 64.716 15.12 ;
     RECT  63.853 15.12 64.692 15.144 ;
     RECT  63.853 15.144 64.716 15.216 ;
     RECT  63.853 15.216 64.692 15.24 ;
     RECT  63.853 15.24 64.716 15.312 ;
     RECT  63.853 15.312 64.692 15.336 ;
     RECT  63.853 15.336 64.716 15.408 ;
     RECT  63.853 15.408 64.692 15.432 ;
     RECT  63.853 15.432 64.716 15.504 ;
     RECT  63.853 15.504 64.692 15.528 ;
     RECT  63.853 15.528 64.716 15.6 ;
     RECT  63.853 15.6 64.692 15.624 ;
     RECT  63.853 15.624 64.716 15.696 ;
     RECT  63.853 15.696 64.692 15.72 ;
     RECT  63.853 15.72 64.716 15.792 ;
     RECT  63.853 15.792 64.692 15.816 ;
     RECT  63.853 15.816 64.716 15.888 ;
     RECT  63.853 15.888 64.692 15.912 ;
     RECT  63.853 15.912 64.716 15.984 ;
     RECT  63.853 15.984 64.692 16.008 ;
     RECT  63.853 16.008 64.716 16.08 ;
     RECT  63.853 16.08 64.692 16.104 ;
     RECT  63.853 16.104 64.716 16.176 ;
     RECT  63.853 16.176 64.692 16.2 ;
     RECT  63.853 16.2 64.716 16.272 ;
     RECT  63.853 16.272 64.692 16.296 ;
     RECT  63.853 16.296 64.716 16.368 ;
     RECT  63.853 16.368 64.692 16.392 ;
     RECT  63.853 16.392 64.716 16.464 ;
     RECT  63.853 16.464 64.692 16.488 ;
     RECT  63.853 16.488 64.716 16.56 ;
     RECT  63.853 16.56 64.692 16.584 ;
     RECT  63.853 16.584 64.716 16.656 ;
     RECT  63.853 16.656 64.692 16.68 ;
     RECT  63.853 16.68 64.716 16.752 ;
     RECT  63.853 16.752 64.692 16.776 ;
     RECT  63.853 16.776 64.716 16.848 ;
     RECT  63.853 16.848 64.692 16.872 ;
     RECT  63.853 16.872 64.716 16.944 ;
     RECT  63.853 16.944 64.692 16.968 ;
     RECT  63.853 16.968 64.716 17.04 ;
     RECT  63.853 17.04 64.692 17.064 ;
     RECT  63.853 17.064 64.716 17.136 ;
     RECT  63.853 17.136 64.692 17.16 ;
     RECT  63.853 17.16 64.716 17.232 ;
     RECT  63.853 17.232 64.692 17.256 ;
     RECT  63.853 17.256 64.716 17.328 ;
     RECT  63.853 17.328 64.692 17.352 ;
     RECT  63.853 17.352 64.716 17.424 ;
     RECT  63.853 17.424 64.692 17.448 ;
     RECT  63.853 17.448 64.716 17.52 ;
     RECT  63.853 17.52 64.692 17.544 ;
     RECT  63.853 17.544 64.716 17.616 ;
     RECT  63.853 17.616 64.692 17.64 ;
     RECT  63.853 17.64 64.716 17.712 ;
     RECT  63.853 17.712 64.692 17.736 ;
     RECT  63.853 17.736 64.716 17.808 ;
     RECT  63.853 17.808 64.692 17.832 ;
     RECT  63.853 17.832 64.716 17.904 ;
     RECT  63.853 17.904 64.692 17.928 ;
     RECT  63.853 17.928 64.716 18 ;
     RECT  63.853 18 64.692 18.024 ;
     RECT  63.853 18.024 64.716 18.096 ;
     RECT  63.853 18.096 64.692 18.12 ;
     RECT  63.853 18.12 64.716 18.192 ;
     RECT  63.853 18.192 64.692 18.216 ;
     RECT  63.853 18.216 64.716 18.288 ;
     RECT  63.853 18.288 64.692 18.312 ;
     RECT  63.853 18.312 64.716 18.384 ;
     RECT  63.853 18.384 64.692 18.408 ;
     RECT  63.853 18.408 64.716 18.48 ;
     RECT  63.853 18.48 64.692 18.504 ;
     RECT  63.853 18.504 64.716 18.576 ;
     RECT  63.853 18.576 64.692 18.6 ;
     RECT  63.853 18.6 64.716 18.672 ;
     RECT  63.853 18.672 64.692 18.696 ;
     RECT  63.853 18.696 64.716 18.768 ;
     RECT  63.853 18.768 64.692 18.792 ;
     RECT  63.853 18.792 64.716 18.864 ;
     RECT  63.853 18.864 64.692 18.888 ;
     RECT  63.853 18.888 64.716 18.96 ;
     RECT  63.853 18.96 64.692 18.984 ;
     RECT  63.853 18.984 64.716 19.056 ;
     RECT  63.853 19.056 64.692 19.08 ;
     RECT  64.716 9.504 64.757 9.528 ;
     RECT  64.716 15.84 64.757 15.888 ;
     RECT  64.716 15.912 64.757 15.984 ;
     RECT  64.716 16.008 64.757 16.08 ;
     RECT  64.716 16.104 64.757 16.176 ;
     RECT  64.716 16.2 64.757 16.272 ;
     RECT  64.716 16.296 64.757 16.368 ;
     RECT  64.716 16.392 64.757 16.464 ;
     RECT  64.716 16.488 64.757 16.56 ;
     RECT  64.716 16.584 64.757 16.656 ;
     RECT  64.716 16.68 64.757 16.752 ;
     RECT  64.716 16.776 64.757 16.848 ;
     RECT  64.716 16.872 64.757 16.944 ;
     RECT  64.716 16.968 64.757 17.04 ;
     RECT  64.716 17.064 64.757 17.136 ;
     RECT  64.716 17.16 64.757 17.232 ;
     RECT  64.716 17.256 64.757 17.328 ;
     RECT  64.716 17.352 64.757 17.424 ;
     RECT  64.716 17.448 64.757 17.52 ;
     RECT  64.716 17.544 64.757 17.616 ;
     RECT  64.716 17.64 64.757 17.712 ;
     RECT  64.716 17.736 64.757 17.808 ;
     RECT  64.716 17.832 64.757 17.88 ;
    LAYER M5 ;
     RECT  2.4 2.137 2.52 2.151 ;
     RECT  5.1 2.137 5.22 2.151 ;
     RECT  7.8 2.137 7.92 2.151 ;
     RECT  10.5 2.137 10.62 2.151 ;
     RECT  13.2 2.137 13.32 2.151 ;
     RECT  15.9 2.137 16.02 2.151 ;
     RECT  18.6 2.137 18.72 2.151 ;
     RECT  21.3 2.137 21.42 2.151 ;
     RECT  24 2.137 24.12 2.151 ;
     RECT  26.7 2.137 26.82 2.151 ;
     RECT  29.4 2.137 29.52 2.151 ;
     RECT  32.1 2.137 32.22 2.151 ;
     RECT  34.8 2.137 34.92 2.151 ;
     RECT  37.5 2.137 37.62 2.151 ;
     RECT  40.2 2.137 40.32 2.151 ;
     RECT  42.9 2.137 43.02 2.151 ;
     RECT  45.6 2.137 45.72 2.151 ;
     RECT  48.3 2.137 48.42 2.151 ;
     RECT  51 2.137 51.12 2.151 ;
     RECT  53.7 2.137 53.82 2.151 ;
     RECT  56.4 2.137 56.52 2.151 ;
     RECT  59.1 2.137 59.22 2.151 ;
     RECT  61.8 2.137 61.92 2.151 ;
     RECT  56.4 2.151 56.712 7.381 ;
     RECT  59.1 2.151 59.412 7.381 ;
     RECT  55.824 7.381 56.808 8.003 ;
     RECT  58.464 7.381 59.412 8.485 ;
     RECT  58.464 8.485 59.928 8.963 ;
     RECT  59.1 8.963 59.928 9.061 ;
     RECT  55.824 8.003 56.712 9.349 ;
     RECT  34.8 2.151 35.112 10.213 ;
     RECT  55.536 9.349 57.048 10.645 ;
     RECT  29.4 2.151 29.712 10.741 ;
     RECT  34.8 10.213 35.208 10.789 ;
     RECT  29.4 10.741 29.832 11.365 ;
     RECT  59.1 9.061 60.36 11.459 ;
     RECT  55.536 10.645 57.432 11.509 ;
     RECT  32.1 2.151 32.412 11.893 ;
     RECT  55.296 11.509 57.432 11.939 ;
     RECT  34.8 10.789 35.496 11.941 ;
     RECT  29.4 11.365 30.12 12.229 ;
     RECT  31.152 11.893 32.412 12.229 ;
     RECT  53.7 2.151 54.012 12.517 ;
     RECT  55.296 11.939 55.32 12.517 ;
     RECT  45.6 2.151 45.912 12.565 ;
     RECT  45.6 12.565 46.872 12.851 ;
     RECT  53.7 12.517 55.32 12.851 ;
     RECT  55.296 12.851 55.32 13.379 ;
     RECT  38.784 13.285 38.808 13.427 ;
     RECT  45.6 12.851 46.776 13.427 ;
     RECT  2.4 2.151 2.712 13.525 ;
     RECT  24 2.151 24.312 13.525 ;
     RECT  45.6 13.427 45.912 13.525 ;
     RECT  29.4 12.229 32.412 13.621 ;
     RECT  56.4 11.939 57.432 13.621 ;
     RECT  23.904 13.525 24.312 13.667 ;
     RECT  60.384 13.045 60.408 13.907 ;
     RECT  34.8 11.941 35.592 14.005 ;
     RECT  56.4 13.621 57.528 14.101 ;
     RECT  34.128 14.005 35.592 14.197 ;
     RECT  2.4 13.525 2.856 14.435 ;
     RECT  56.4 14.101 57.912 14.629 ;
     RECT  59.1 11.459 59.412 14.629 ;
     RECT  0.144 13.861 0.168 14.725 ;
     RECT  29.4 13.621 32.808 14.773 ;
     RECT  56.4 14.629 59.412 14.773 ;
     RECT  0.144 14.725 0.264 14.867 ;
     RECT  0.24 14.867 0.264 14.963 ;
     RECT  55.632 14.773 59.412 15.443 ;
     RECT  34.128 14.197 36.072 15.445 ;
     RECT  34.128 15.445 36.264 15.493 ;
     RECT  34.128 15.493 36.456 15.733 ;
     RECT  37.5 2.151 37.812 15.733 ;
     RECT  29.4 14.773 32.904 15.781 ;
     RECT  34.128 15.733 37.812 15.781 ;
     RECT  29.4 15.781 37.812 15.973 ;
     RECT  44.976 13.525 45.912 16.309 ;
     RECT  29.4 15.973 37.944 16.453 ;
     RECT  29.4 16.453 38.088 16.549 ;
     RECT  56.4 15.443 59.412 16.595 ;
     RECT  58.32 16.595 59.412 16.883 ;
     RECT  44.976 16.309 46.104 17.077 ;
     RECT  44.832 17.077 46.104 17.651 ;
     RECT  26.7 2.151 27.012 17.653 ;
     RECT  58.656 16.883 59.412 17.843 ;
     RECT  26.7 17.653 27.144 18.037 ;
     RECT  26.7 18.037 28.008 18.517 ;
     RECT  26.592 18.517 28.008 18.565 ;
     RECT  47.28 17.077 47.304 18.757 ;
     RECT  48.3 2.151 48.612 18.757 ;
     RECT  47.28 18.757 48.612 18.851 ;
     RECT  56.4 16.595 56.904 18.851 ;
     RECT  60.384 18.565 60.408 18.995 ;
     RECT  58.992 17.843 59.412 19.283 ;
     RECT  26.592 18.565 28.2 20.533 ;
     RECT  29.4 16.549 38.568 20.533 ;
     RECT  45.456 17.651 46.104 21.155 ;
     RECT  26.592 20.533 38.568 21.637 ;
     RECT  26.592 21.637 38.664 24.085 ;
     RECT  26.496 24.085 38.664 24.421 ;
     RECT  47.904 18.851 48.612 26.627 ;
     RECT  2.4 14.435 2.712 27.819 ;
     RECT  5.1 2.151 5.412 27.819 ;
     RECT  7.8 2.151 8.112 27.819 ;
     RECT  10.5 2.151 10.812 27.819 ;
     RECT  13.2 2.151 13.512 27.819 ;
     RECT  15.9 2.151 16.212 27.819 ;
     RECT  18.6 2.151 18.912 27.819 ;
     RECT  21.3 2.151 21.612 27.819 ;
     RECT  24 13.667 24.312 27.819 ;
     RECT  40.2 2.151 40.512 27.819 ;
     RECT  42.9 2.151 43.212 27.819 ;
     RECT  45.6 21.155 45.912 27.819 ;
     RECT  48.3 26.627 48.612 27.819 ;
     RECT  51 2.151 51.312 27.819 ;
     RECT  53.7 12.851 54.012 27.819 ;
     RECT  56.4 18.851 56.712 27.819 ;
     RECT  59.1 19.283 59.412 27.819 ;
     RECT  61.8 2.151 62.112 27.819 ;
     RECT  2.592 27.819 2.712 27.833 ;
     RECT  5.292 27.819 5.412 27.833 ;
     RECT  7.992 27.819 8.112 27.833 ;
     RECT  10.692 27.819 10.812 27.833 ;
     RECT  13.392 27.819 13.512 27.833 ;
     RECT  16.092 27.819 16.212 27.833 ;
     RECT  18.792 27.819 18.912 27.833 ;
     RECT  21.492 27.819 21.612 27.833 ;
     RECT  24.192 27.819 24.312 27.833 ;
     RECT  40.392 27.819 40.512 27.833 ;
     RECT  43.092 27.819 43.212 27.833 ;
     RECT  45.792 27.819 45.912 27.833 ;
     RECT  48.492 27.819 48.612 27.833 ;
     RECT  51.192 27.819 51.312 27.833 ;
     RECT  53.892 27.819 54.012 27.833 ;
     RECT  56.592 27.819 56.712 27.833 ;
     RECT  59.292 27.819 59.412 27.833 ;
     RECT  61.992 27.819 62.112 27.833 ;
     RECT  26.448 24.421 38.664 29.029 ;
     RECT  26.352 29.029 38.664 30.132 ;
     RECT  26.376 30.132 26.448 30.16 ;
     RECT  26.472 30.132 26.544 30.16 ;
     RECT  26.568 30.132 26.64 30.16 ;
     RECT  26.664 30.132 26.736 30.16 ;
     RECT  26.76 30.132 26.832 30.16 ;
     RECT  26.856 30.132 26.928 30.16 ;
     RECT  26.952 30.132 27.024 30.16 ;
     RECT  27.048 30.132 27.12 30.16 ;
     RECT  27.144 30.132 27.216 30.16 ;
     RECT  27.24 30.132 27.312 30.16 ;
     RECT  27.336 30.132 27.408 30.16 ;
     RECT  27.432 30.132 27.504 30.16 ;
     RECT  27.528 30.132 27.6 30.16 ;
     RECT  27.624 30.132 27.696 30.16 ;
     RECT  27.72 30.132 27.792 30.16 ;
     RECT  27.816 30.132 27.888 30.16 ;
     RECT  27.912 30.132 27.984 30.16 ;
     RECT  28.008 30.132 28.08 30.16 ;
     RECT  28.104 30.132 28.176 30.16 ;
     RECT  28.2 30.132 28.272 30.16 ;
     RECT  28.296 30.132 28.368 30.16 ;
     RECT  28.392 30.132 28.464 30.16 ;
     RECT  28.488 30.132 28.56 30.16 ;
     RECT  28.584 30.132 28.656 30.16 ;
     RECT  28.68 30.132 28.752 30.16 ;
     RECT  28.776 30.132 28.848 30.16 ;
     RECT  28.872 30.132 28.944 30.16 ;
     RECT  28.968 30.132 29.04 30.16 ;
     RECT  29.064 30.132 29.136 30.16 ;
     RECT  29.16 30.132 29.232 30.16 ;
     RECT  29.256 30.132 29.328 30.16 ;
     RECT  29.352 30.132 29.424 30.16 ;
     RECT  29.448 30.132 29.52 30.16 ;
     RECT  29.544 30.132 29.616 30.16 ;
     RECT  29.64 30.132 29.712 30.16 ;
     RECT  29.736 30.132 29.808 30.16 ;
     RECT  29.832 30.132 29.904 30.16 ;
     RECT  29.928 30.132 30 30.16 ;
     RECT  30.024 30.132 30.096 30.16 ;
     RECT  30.12 30.132 30.192 30.16 ;
     RECT  30.216 30.132 30.288 30.16 ;
     RECT  30.312 30.132 30.384 30.16 ;
     RECT  30.408 30.132 30.48 30.16 ;
     RECT  30.504 30.132 30.576 30.16 ;
     RECT  30.6 30.132 30.672 30.16 ;
     RECT  30.696 30.132 30.768 30.16 ;
     RECT  30.792 30.132 30.864 30.16 ;
     RECT  30.888 30.132 30.96 30.16 ;
     RECT  30.984 30.132 31.056 30.16 ;
     RECT  31.08 30.132 31.152 30.16 ;
     RECT  31.176 30.132 31.248 30.16 ;
     RECT  31.272 30.132 31.344 30.16 ;
     RECT  31.368 30.132 31.44 30.16 ;
     RECT  31.464 30.132 31.536 30.16 ;
     RECT  31.56 30.132 31.632 30.16 ;
     RECT  31.656 30.132 31.728 30.16 ;
     RECT  31.752 30.132 31.824 30.16 ;
     RECT  31.848 30.132 31.92 30.16 ;
     RECT  31.944 30.132 32.016 30.16 ;
     RECT  32.04 30.132 32.112 30.16 ;
     RECT  32.136 30.132 32.208 30.16 ;
     RECT  32.232 30.132 32.304 30.16 ;
     RECT  32.328 30.132 32.4 30.16 ;
     RECT  32.424 30.132 32.496 30.16 ;
     RECT  32.52 30.132 32.592 30.16 ;
     RECT  32.616 30.132 32.688 30.16 ;
     RECT  32.712 30.132 32.784 30.16 ;
     RECT  32.808 30.132 32.88 30.16 ;
     RECT  32.904 30.132 32.976 30.16 ;
     RECT  33 30.132 33.072 30.16 ;
     RECT  33.096 30.132 33.168 30.16 ;
     RECT  33.192 30.132 33.264 30.16 ;
     RECT  33.288 30.132 33.36 30.16 ;
     RECT  33.384 30.132 33.456 30.16 ;
     RECT  33.48 30.132 33.552 30.16 ;
     RECT  33.576 30.132 33.648 30.16 ;
     RECT  33.672 30.132 33.744 30.16 ;
     RECT  33.768 30.132 33.84 30.16 ;
     RECT  33.864 30.132 33.936 30.16 ;
     RECT  33.96 30.132 34.032 30.16 ;
     RECT  34.056 30.132 34.128 30.16 ;
     RECT  34.152 30.132 34.224 30.16 ;
     RECT  34.248 30.132 34.32 30.16 ;
     RECT  34.344 30.132 34.416 30.16 ;
     RECT  34.44 30.132 34.512 30.16 ;
     RECT  34.536 30.132 34.608 30.16 ;
     RECT  34.632 30.132 34.704 30.16 ;
     RECT  34.728 30.132 34.8 30.16 ;
     RECT  34.824 30.132 34.896 30.16 ;
     RECT  34.92 30.132 34.992 30.16 ;
     RECT  35.016 30.132 35.088 30.16 ;
     RECT  35.112 30.132 35.184 30.16 ;
     RECT  35.208 30.132 35.28 30.16 ;
     RECT  35.304 30.132 35.376 30.16 ;
     RECT  35.4 30.132 35.472 30.16 ;
     RECT  35.496 30.132 35.568 30.16 ;
     RECT  35.592 30.132 35.664 30.16 ;
     RECT  35.688 30.132 35.76 30.16 ;
     RECT  35.784 30.132 35.856 30.16 ;
     RECT  35.88 30.132 35.952 30.16 ;
     RECT  35.976 30.132 36.048 30.16 ;
     RECT  36.072 30.132 36.144 30.16 ;
     RECT  36.168 30.132 36.24 30.16 ;
     RECT  36.264 30.132 36.336 30.16 ;
     RECT  36.36 30.132 36.432 30.16 ;
     RECT  36.456 30.132 36.528 30.16 ;
     RECT  36.552 30.132 36.624 30.16 ;
     RECT  36.648 30.132 36.72 30.16 ;
     RECT  36.744 30.132 36.816 30.16 ;
     RECT  36.84 30.132 36.912 30.16 ;
     RECT  36.936 30.132 37.008 30.16 ;
     RECT  37.032 30.132 37.104 30.16 ;
     RECT  37.128 30.132 37.2 30.16 ;
     RECT  37.224 30.132 37.296 30.16 ;
     RECT  37.32 30.132 37.392 30.16 ;
     RECT  37.416 30.132 37.488 30.16 ;
     RECT  37.512 30.132 37.584 30.16 ;
     RECT  37.608 30.132 37.68 30.16 ;
     RECT  37.704 30.132 37.776 30.16 ;
     RECT  37.8 30.132 37.872 30.16 ;
     RECT  37.896 30.132 37.968 30.16 ;
     RECT  37.992 30.132 38.064 30.16 ;
     RECT  38.088 30.132 38.16 30.16 ;
     RECT  38.184 30.132 38.256 30.16 ;
     RECT  38.28 30.132 38.352 30.16 ;
     RECT  38.376 30.132 38.448 30.16 ;
     RECT  38.472 30.132 38.544 30.16 ;
     RECT  38.568 30.132 38.64 30.16 ;
     RECT  56.712 8.003 56.808 9.349 ;
     RECT  60.36 9.061 61.8 11.459 ;
     RECT  54.012 9.349 55.536 11.509 ;
     RECT  54.012 11.509 55.296 12.517 ;
     RECT  30.12 11.893 31.152 12.229 ;
     RECT  55.32 11.939 56.4 13.379 ;
     RECT  46.872 12.565 48.3 12.851 ;
     RECT  46.776 12.851 48.3 13.427 ;
     RECT  54.012 12.851 55.296 13.379 ;
     RECT  59.412 13.045 60.384 13.907 ;
     RECT  60.408 13.045 61.8 13.907 ;
     RECT  37.812 13.285 38.784 13.427 ;
     RECT  38.808 13.285 40.2 13.427 ;
     RECT  55.632 13.379 56.4 14.773 ;
     RECT  32.808 14.005 34.128 14.773 ;
     RECT  57.912 14.101 59.1 14.629 ;
     RECT  36.072 14.197 37.5 15.445 ;
     RECT  32.904 14.773 34.128 15.781 ;
     RECT  36.264 15.445 37.5 15.493 ;
     RECT  36.456 15.493 37.5 15.733 ;
     RECT  56.904 16.595 58.32 16.883 ;
     RECT  46.104 17.077 47.28 18.851 ;
     RECT  47.304 17.077 48.3 18.757 ;
     RECT  28.008 18.037 29.4 18.565 ;
     RECT  28.2 18.565 29.4 20.533 ;
     RECT  59.412 18.565 60.384 18.995 ;
     RECT  60.408 18.565 61.8 18.995 ;
  END
END qfd_rlyh0_128_EN_65x30
END LIBRARY
